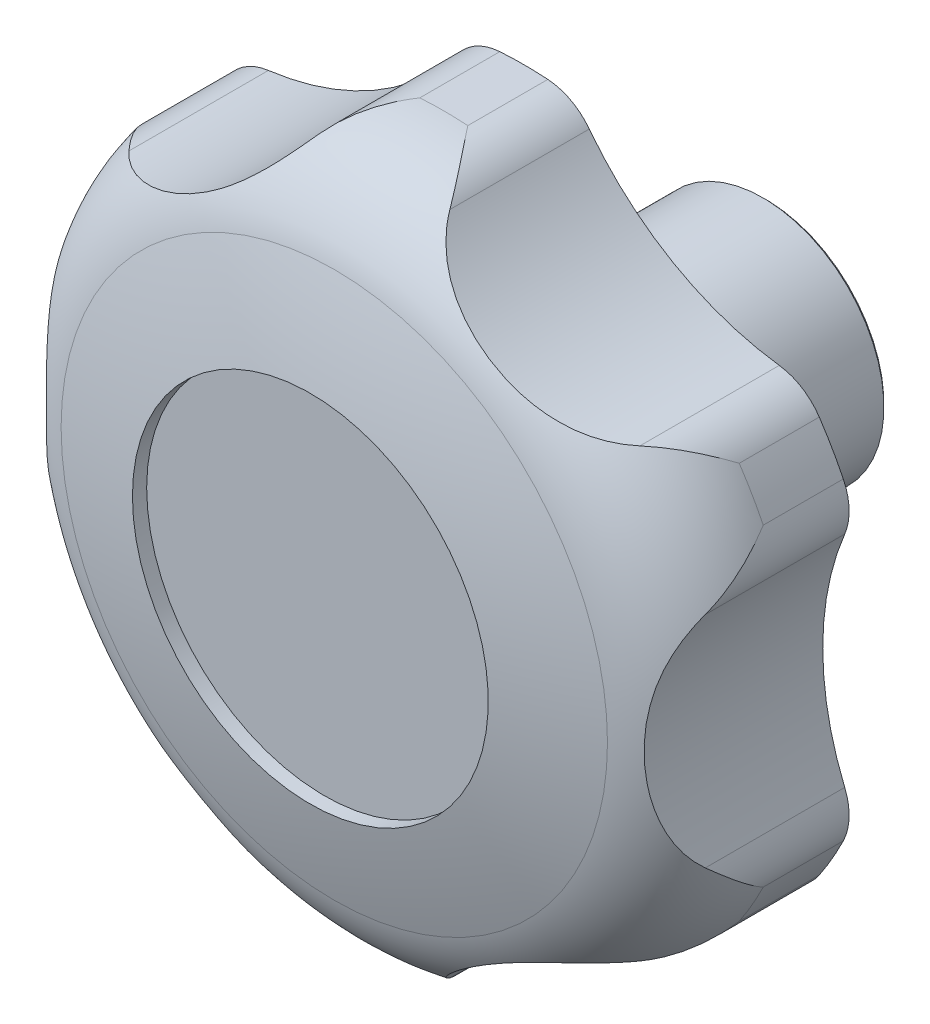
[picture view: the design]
ISO-10303-21;
HEADER;
FILE_DESCRIPTION(('STEP AP214'),'2;1');
FILE_NAME('part.step','',(''),(''),'','','');
FILE_SCHEMA(('AUTOMOTIVE_DESIGN { 1 0 10303 214 1 1 1 1 }'));
ENDSEC;
DATA;
#1=APPLICATION_CONTEXT('core data for automotive mechanical design processes');
#2=APPLICATION_PROTOCOL_DEFINITION('international standard','automotive_design',2000,#1);
#3=PRODUCT_CONTEXT('',#1,'mechanical');
#4=PRODUCT('Part','Part','',(#3));
#5=PRODUCT_RELATED_PRODUCT_CATEGORY('part','',(#4));
#6=PRODUCT_DEFINITION_FORMATION('','',#4);
#7=PRODUCT_DEFINITION_CONTEXT('part definition',#1,'design');
#8=PRODUCT_DEFINITION('design','',#6,#7);
#9=PRODUCT_DEFINITION_SHAPE('','',#8);
#10=(LENGTH_UNIT() NAMED_UNIT(*) SI_UNIT(.MILLI.,.METRE.));
#11=(NAMED_UNIT(*) PLANE_ANGLE_UNIT() SI_UNIT($,.RADIAN.));
#12=(NAMED_UNIT(*) SI_UNIT($,.STERADIAN.) SOLID_ANGLE_UNIT());
#13=UNCERTAINTY_MEASURE_WITH_UNIT(LENGTH_MEASURE(1.E-05),#10,'distance_accuracy_value','');
#14=(GEOMETRIC_REPRESENTATION_CONTEXT(3) GLOBAL_UNCERTAINTY_ASSIGNED_CONTEXT((#13)) GLOBAL_UNIT_ASSIGNED_CONTEXT((#10,
#11,#12)) REPRESENTATION_CONTEXT('',''));
#15=CARTESIAN_POINT('',(0.,0.,0.));
#16=DIRECTION('',(0.,0.,1.));
#17=DIRECTION('',(1.,0.,0.));
#18=AXIS2_PLACEMENT_3D('',#15,#16,#17);
#19=CARTESIAN_POINT('',(0.,0.,39.106347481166));
#20=DIRECTION('',(0.,0.,1.));
#21=DIRECTION('',(-1.,0.,0.));
#22=AXIS2_PLACEMENT_3D('',#19,#20,#21);
#23=CYLINDRICAL_SURFACE('',#22,25.);
#24=CARTESIAN_POINT('',(0.,0.,17.));
#25=DIRECTION('',(0.,0.,1.));
#26=DIRECTION('',(-1.,0.,0.));
#27=AXIS2_PLACEMENT_3D('',#24,#25,#26);
#28=CIRCLE('',#27,25.);
#29=CARTESIAN_POINT('',(1.68710504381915,24.9430085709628,17.));
#30=VERTEX_POINT('',#29);
#31=CARTESIAN_POINT('',(-1.68710504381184,24.9430085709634,17.));
#32=VERTEX_POINT('',#31);
#33=EDGE_CURVE('E418',#30,#32,#28,.T.);
#34=ORIENTED_EDGE('',*,*,#33,.T.);
#35=DIRECTION('',(0.,0.,1.));
#36=VECTOR('',#35,1.);
#37=CARTESIAN_POINT('',(-1.68710504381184,24.9430085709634,0.));
#38=LINE('',#37,#36);
#39=CARTESIAN_POINT('',(-1.68710504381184,24.9430085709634,22.6238207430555));
#40=VERTEX_POINT('',#39);
#41=EDGE_CURVE('E214',#32,#40,#38,.T.);
#42=ORIENTED_EDGE('',*,*,#41,.T.);
#43=CARTESIAN_POINT('',(0.,0.,22.6238207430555));
#44=DIRECTION('',(0.,0.,1.));
#45=DIRECTION('',(-1.,0.,0.));
#46=AXIS2_PLACEMENT_3D('',#43,#44,#45);
#47=CIRCLE('',#46,25.);
#48=CARTESIAN_POINT('',(1.68710504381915,24.9430085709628,22.6238207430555));
#49=VERTEX_POINT('',#48);
#50=EDGE_CURVE('E433',#49,#40,#47,.T.);
#51=ORIENTED_EDGE('',*,*,#50,.F.);
#52=DIRECTION('',(0.,0.,1.));
#53=VECTOR('',#52,1.);
#54=CARTESIAN_POINT('',(1.68710504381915,24.9430085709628,0.));
#55=LINE('',#54,#53);
#56=EDGE_CURVE('E465',#30,#49,#55,.T.);
#57=ORIENTED_EDGE('',*,*,#56,.F.);
#58=EDGE_LOOP('',(#34,#42,#51,#57));
#59=FACE_BOUND('',#58,.T.);
#60=ADVANCED_FACE('F14',(#59),#23,.T.);
#61=CARTESIAN_POINT('',(22.444831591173,11.0104284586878,17.));
#62=VERTEX_POINT('',#61);
#63=CARTESIAN_POINT('',(20.7577265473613,13.9325801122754,17.));
#64=VERTEX_POINT('',#63);
#65=EDGE_CURVE('E422',#62,#64,#28,.T.);
#66=ORIENTED_EDGE('',*,*,#65,.T.);
#67=DIRECTION('',(0.,0.,1.));
#68=VECTOR('',#67,1.);
#69=CARTESIAN_POINT('',(20.7577265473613,13.9325801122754,0.));
#70=LINE('',#69,#68);
#71=CARTESIAN_POINT('',(20.7577265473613,13.9325801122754,22.6238207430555));
#72=VERTEX_POINT('',#71);
#73=EDGE_CURVE('E450',#64,#72,#70,.T.);
#74=ORIENTED_EDGE('',*,*,#73,.T.);
#75=CARTESIAN_POINT('',(22.444831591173,11.0104284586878,22.6238207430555));
#76=VERTEX_POINT('',#75);
#77=EDGE_CURVE('E480',#76,#72,#47,.T.);
#78=ORIENTED_EDGE('',*,*,#77,.F.);
#79=DIRECTION('',(0.,0.,1.));
#80=VECTOR('',#79,1.);
#81=CARTESIAN_POINT('',(22.444831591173,11.0104284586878,0.));
#82=LINE('',#81,#80);
#83=EDGE_CURVE('E452',#62,#76,#82,.T.);
#84=ORIENTED_EDGE('',*,*,#83,.F.);
#85=EDGE_LOOP('',(#66,#74,#78,#84));
#86=FACE_BOUND('',#85,.T.);
#87=ADVANCED_FACE('F393',(#86),#23,.T.);
#88=CARTESIAN_POINT('',(20.7577265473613,-13.9325801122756,17.));
#89=VERTEX_POINT('',#88);
#90=CARTESIAN_POINT('',(22.444831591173,-11.0104284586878,17.));
#91=VERTEX_POINT('',#90);
#92=EDGE_CURVE('E436',#89,#91,#28,.T.);
#93=ORIENTED_EDGE('',*,*,#92,.T.);
#94=DIRECTION('',(0.,0.,1.));
#95=VECTOR('',#94,1.);
#96=CARTESIAN_POINT('',(22.444831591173,-11.0104284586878,0.));
#97=LINE('',#96,#95);
#98=CARTESIAN_POINT('',(22.444831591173,-11.0104284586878,22.6238207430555));
#99=VERTEX_POINT('',#98);
#100=EDGE_CURVE('E534',#91,#99,#97,.T.);
#101=ORIENTED_EDGE('',*,*,#100,.T.);
#102=CARTESIAN_POINT('',(20.7577265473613,-13.9325801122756,22.6238207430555));
#103=VERTEX_POINT('',#102);
#104=EDGE_CURVE('E481',#103,#99,#47,.T.);
#105=ORIENTED_EDGE('',*,*,#104,.F.);
#106=DIRECTION('',(0.,0.,1.));
#107=VECTOR('',#106,1.);
#108=CARTESIAN_POINT('',(20.7577265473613,-13.9325801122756,0.));
#109=LINE('',#108,#107);
#110=EDGE_CURVE('E532',#89,#103,#109,.T.);
#111=ORIENTED_EDGE('',*,*,#110,.F.);
#112=EDGE_LOOP('',(#93,#101,#105,#111));
#113=FACE_BOUND('',#112,.T.);
#114=ADVANCED_FACE('F401',(#113),#23,.T.);
#115=CARTESIAN_POINT('',(-1.68710504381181,-24.9430085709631,17.));
#116=VERTEX_POINT('',#115);
#117=CARTESIAN_POINT('',(1.68710504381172,-24.9430085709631,17.));
#118=VERTEX_POINT('',#117);
#119=EDGE_CURVE('E429',#116,#118,#28,.T.);
#120=ORIENTED_EDGE('',*,*,#119,.T.);
#121=DIRECTION('',(0.,0.,1.));
#122=VECTOR('',#121,1.);
#123=CARTESIAN_POINT('',(1.68710504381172,-24.9430085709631,0.));
#124=LINE('',#123,#122);
#125=CARTESIAN_POINT('',(1.68710504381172,-24.9430085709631,22.6238207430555));
#126=VERTEX_POINT('',#125);
#127=EDGE_CURVE('E524',#118,#126,#124,.T.);
#128=ORIENTED_EDGE('',*,*,#127,.T.);
#129=CARTESIAN_POINT('',(-1.68710504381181,-24.9430085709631,22.6238207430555));
#130=VERTEX_POINT('',#129);
#131=EDGE_CURVE('E485',#130,#126,#47,.T.);
#132=ORIENTED_EDGE('',*,*,#131,.F.);
#133=DIRECTION('',(0.,0.,1.));
#134=VECTOR('',#133,1.);
#135=CARTESIAN_POINT('',(-1.68710504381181,-24.9430085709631,0.));
#136=LINE('',#135,#134);
#137=EDGE_CURVE('E522',#116,#130,#136,.T.);
#138=ORIENTED_EDGE('',*,*,#137,.F.);
#139=EDGE_LOOP('',(#120,#128,#132,#138));
#140=FACE_BOUND('',#139,.T.);
#141=ADVANCED_FACE('F413',(#140),#23,.T.);
#142=CARTESIAN_POINT('',(-22.4448315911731,-11.0104284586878,17.));
#143=VERTEX_POINT('',#142);
#144=CARTESIAN_POINT('',(-20.7577265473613,-13.9325801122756,17.));
#145=VERTEX_POINT('',#144);
#146=EDGE_CURVE('E421',#143,#145,#28,.T.);
#147=ORIENTED_EDGE('',*,*,#146,.T.);
#148=DIRECTION('',(0.,0.,1.));
#149=VECTOR('',#148,1.);
#150=CARTESIAN_POINT('',(-20.7577265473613,-13.9325801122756,0.));
#151=LINE('',#150,#149);
#152=CARTESIAN_POINT('',(-20.7577265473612,-13.9325801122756,22.6238207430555));
#153=VERTEX_POINT('',#152);
#154=EDGE_CURVE('E514',#145,#153,#151,.T.);
#155=ORIENTED_EDGE('',*,*,#154,.T.);
#156=CARTESIAN_POINT('',(-22.4448315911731,-11.0104284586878,22.6238207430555));
#157=VERTEX_POINT('',#156);
#158=EDGE_CURVE('E434',#157,#153,#47,.T.);
#159=ORIENTED_EDGE('',*,*,#158,.F.);
#160=DIRECTION('',(0.,0.,1.));
#161=VECTOR('',#160,1.);
#162=CARTESIAN_POINT('',(-22.4448315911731,-11.0104284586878,0.));
#163=LINE('',#162,#161);
#164=EDGE_CURVE('E512',#143,#157,#163,.T.);
#165=ORIENTED_EDGE('',*,*,#164,.F.);
#166=EDGE_LOOP('',(#147,#155,#159,#165));
#167=FACE_BOUND('',#166,.T.);
#168=ADVANCED_FACE('F405',(#167),#23,.T.);
#169=CARTESIAN_POINT('',(-20.7577265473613,13.9325801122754,17.));
#170=VERTEX_POINT('',#169);
#171=CARTESIAN_POINT('',(-22.4448315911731,11.0104284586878,17.));
#172=VERTEX_POINT('',#171);
#173=EDGE_CURVE('E210',#170,#172,#28,.T.);
#174=ORIENTED_EDGE('',*,*,#173,.T.);
#175=DIRECTION('',(0.,0.,1.));
#176=VECTOR('',#175,1.);
#177=CARTESIAN_POINT('',(-22.4448315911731,11.0104284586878,0.));
#178=LINE('',#177,#176);
#179=CARTESIAN_POINT('',(-22.4448315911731,11.0104284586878,22.6238207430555));
#180=VERTEX_POINT('',#179);
#181=EDGE_CURVE('E416',#172,#180,#178,.T.);
#182=ORIENTED_EDGE('',*,*,#181,.T.);
#183=CARTESIAN_POINT('',(-20.7577265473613,13.9325801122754,22.6238207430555));
#184=VERTEX_POINT('',#183);
#185=EDGE_CURVE('E428',#184,#180,#47,.T.);
#186=ORIENTED_EDGE('',*,*,#185,.F.);
#187=DIRECTION('',(0.,0.,1.));
#188=VECTOR('',#187,1.);
#189=CARTESIAN_POINT('',(-20.7577265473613,13.9325801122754,0.));
#190=LINE('',#189,#188);
#191=EDGE_CURVE('E203',#170,#184,#190,.T.);
#192=ORIENTED_EDGE('',*,*,#191,.F.);
#193=EDGE_LOOP('',(#174,#182,#186,#192));
#194=FACE_BOUND('',#193,.T.);
#195=ADVANCED_FACE('F395',(#194),#23,.T.);
#196=CARTESIAN_POINT('',(0.,11.,17.));
#197=DIRECTION('',(0.,0.,1.));
#198=DIRECTION('',(-1.,0.,0.));
#199=AXIS2_PLACEMENT_3D('',#196,#197,#198);
#200=PLANE('',#199);
#201=ORIENTED_EDGE('',*,*,#33,.F.);
#202=CARTESIAN_POINT('',(1.41716823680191,20.9521271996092,17.));
#203=DIRECTION('',(0.,0.,1.));
#204=DIRECTION('',(-1.,0.,0.));
#205=AXIS2_PLACEMENT_3D('',#202,#203,#204);
#206=CIRCLE('',#205,4.);
#207=CARTESIAN_POINT('',(4.59764019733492,23.377946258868,17.));
#208=VERTEX_POINT('',#207);
#209=EDGE_CURVE('E379',#30,#208,#206,.F.);
#210=ORIENTED_EDGE('',*,*,#209,.T.);
#211=CARTESIAN_POINT('',(20.5,35.507041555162,17.));
#212=DIRECTION('',(0.,0.,1.));
#213=DIRECTION('',(-1.,0.,0.));
#214=AXIS2_PLACEMENT_3D('',#211,#212,#213);
#215=CIRCLE('',#214,20.);
#216=CARTESIAN_POINT('',(17.9470752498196,15.6706463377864,17.));
#217=VERTEX_POINT('',#216);
#218=EDGE_CURVE('E457',#217,#208,#215,.F.);
#219=ORIENTED_EDGE('',*,*,#218,.F.);
#220=CARTESIAN_POINT('',(17.4364902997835,11.7033672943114,17.));
#221=DIRECTION('',(0.,0.,1.));
#222=DIRECTION('',(-1.,0.,0.));
#223=AXIS2_PLACEMENT_3D('',#220,#221,#222);
#224=CIRCLE('',#223,4.);
#225=EDGE_CURVE('E370',#217,#64,#224,.F.);
#226=ORIENTED_EDGE('',*,*,#225,.T.);
#227=ORIENTED_EDGE('',*,*,#65,.F.);
#228=CARTESIAN_POINT('',(18.8536585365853,9.24875990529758,17.));
#229=DIRECTION('',(0.,0.,1.));
#230=DIRECTION('',(-1.,0.,0.));
#231=AXIS2_PLACEMENT_3D('',#228,#229,#230);
#232=CIRCLE('',#231,4.);
#233=CARTESIAN_POINT('',(22.5447154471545,7.70729992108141,17.));
#234=VERTEX_POINT('',#233);
#235=EDGE_CURVE('E352',#62,#234,#232,.F.);
#236=ORIENTED_EDGE('',*,*,#235,.T.);
#237=CARTESIAN_POINT('',(41.,0.,17.));
#238=DIRECTION('',(0.,0.,1.));
#239=DIRECTION('',(-1.,0.,0.));
#240=AXIS2_PLACEMENT_3D('',#237,#238,#239);
#241=CIRCLE('',#240,20.);
#242=CARTESIAN_POINT('',(22.5447154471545,-7.70729992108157,17.));
#243=VERTEX_POINT('',#242);
#244=EDGE_CURVE('E564',#243,#234,#241,.F.);
#245=ORIENTED_EDGE('',*,*,#244,.F.);
#246=CARTESIAN_POINT('',(18.8536585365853,-9.2487599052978,17.));
#247=DIRECTION('',(0.,0.,1.));
#248=DIRECTION('',(-1.,0.,0.));
#249=AXIS2_PLACEMENT_3D('',#246,#247,#248);
#250=CIRCLE('',#249,4.);
#251=EDGE_CURVE('E343',#243,#91,#250,.F.);
#252=ORIENTED_EDGE('',*,*,#251,.T.);
#253=ORIENTED_EDGE('',*,*,#92,.F.);
#254=CARTESIAN_POINT('',(17.4364902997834,-11.7033672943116,17.));
#255=DIRECTION('',(0.,0.,1.));
#256=DIRECTION('',(-1.,0.,0.));
#257=AXIS2_PLACEMENT_3D('',#254,#255,#256);
#258=CIRCLE('',#257,4.);
#259=CARTESIAN_POINT('',(17.9470752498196,-15.6706463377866,17.));
#260=VERTEX_POINT('',#259);
#261=EDGE_CURVE('E320',#89,#260,#258,.F.);
#262=ORIENTED_EDGE('',*,*,#261,.T.);
#263=CARTESIAN_POINT('',(20.5,-35.5070415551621,17.));
#264=DIRECTION('',(0.,0.,1.));
#265=DIRECTION('',(-1.,0.,0.));
#266=AXIS2_PLACEMENT_3D('',#263,#264,#265);
#267=CIRCLE('',#266,20.);
#268=CARTESIAN_POINT('',(4.59764019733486,-23.3779462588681,17.));
#269=VERTEX_POINT('',#268);
#270=EDGE_CURVE('E563',#269,#260,#267,.F.);
#271=ORIENTED_EDGE('',*,*,#270,.F.);
#272=CARTESIAN_POINT('',(1.41716823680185,-20.9521271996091,17.));
#273=DIRECTION('',(0.,0.,1.));
#274=DIRECTION('',(-1.,0.,0.));
#275=AXIS2_PLACEMENT_3D('',#272,#273,#274);
#276=CIRCLE('',#275,4.);
#277=EDGE_CURVE('E310',#269,#118,#276,.F.);
#278=ORIENTED_EDGE('',*,*,#277,.T.);
#279=ORIENTED_EDGE('',*,*,#119,.F.);
#280=CARTESIAN_POINT('',(-1.41716823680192,-20.9521271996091,17.));
#281=DIRECTION('',(0.,0.,1.));
#282=DIRECTION('',(-1.,0.,0.));
#283=AXIS2_PLACEMENT_3D('',#280,#281,#282);
#284=CIRCLE('',#283,4.);
#285=CARTESIAN_POINT('',(-4.59764019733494,-23.3779462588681,17.));
#286=VERTEX_POINT('',#285);
#287=EDGE_CURVE('E299',#116,#286,#284,.F.);
#288=ORIENTED_EDGE('',*,*,#287,.T.);
#289=CARTESIAN_POINT('',(-20.5,-35.5070415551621,17.));
#290=DIRECTION('',(0.,0.,1.));
#291=DIRECTION('',(-1.,0.,0.));
#292=AXIS2_PLACEMENT_3D('',#289,#290,#291);
#293=CIRCLE('',#292,20.);
#294=CARTESIAN_POINT('',(-17.9470752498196,-15.6706463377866,17.));
#295=VERTEX_POINT('',#294);
#296=EDGE_CURVE('E565',#295,#286,#293,.F.);
#297=ORIENTED_EDGE('',*,*,#296,.F.);
#298=CARTESIAN_POINT('',(-17.4364902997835,-11.7033672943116,17.));
#299=DIRECTION('',(0.,0.,1.));
#300=DIRECTION('',(-1.,0.,0.));
#301=AXIS2_PLACEMENT_3D('',#298,#299,#300);
#302=CIRCLE('',#301,4.);
#303=EDGE_CURVE('E300',#295,#145,#302,.F.);
#304=ORIENTED_EDGE('',*,*,#303,.T.);
#305=ORIENTED_EDGE('',*,*,#146,.F.);
#306=CARTESIAN_POINT('',(-18.8536585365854,-9.2487599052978,17.));
#307=DIRECTION('',(0.,0.,1.));
#308=DIRECTION('',(-1.,0.,0.));
#309=AXIS2_PLACEMENT_3D('',#306,#307,#308);
#310=CIRCLE('',#309,4.);
#311=CARTESIAN_POINT('',(-22.5447154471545,-7.70729992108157,17.));
#312=VERTEX_POINT('',#311);
#313=EDGE_CURVE('E794',#143,#312,#310,.F.);
#314=ORIENTED_EDGE('',*,*,#313,.T.);
#315=CARTESIAN_POINT('',(-41.,0.,17.));
#316=DIRECTION('',(0.,0.,1.));
#317=DIRECTION('',(-1.,0.,0.));
#318=AXIS2_PLACEMENT_3D('',#315,#316,#317);
#319=CIRCLE('',#318,20.);
#320=CARTESIAN_POINT('',(-22.5447154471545,7.70729992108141,17.));
#321=VERTEX_POINT('',#320);
#322=EDGE_CURVE('E194',#321,#312,#319,.F.);
#323=ORIENTED_EDGE('',*,*,#322,.F.);
#324=CARTESIAN_POINT('',(-18.8536585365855,9.2487599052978,17.));
#325=DIRECTION('',(0.,0.,1.));
#326=DIRECTION('',(-1.,0.,0.));
#327=AXIS2_PLACEMENT_3D('',#324,#325,#326);
#328=CIRCLE('',#327,4.);
#329=EDGE_CURVE('E212',#321,#172,#328,.F.);
#330=ORIENTED_EDGE('',*,*,#329,.T.);
#331=ORIENTED_EDGE('',*,*,#173,.F.);
#332=CARTESIAN_POINT('',(-17.4364902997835,11.7033672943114,17.));
#333=DIRECTION('',(0.,0.,1.));
#334=DIRECTION('',(-1.,0.,0.));
#335=AXIS2_PLACEMENT_3D('',#332,#333,#334);
#336=CIRCLE('',#335,4.);
#337=CARTESIAN_POINT('',(-17.9470752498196,15.6706463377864,17.));
#338=VERTEX_POINT('',#337);
#339=EDGE_CURVE('E199',#170,#338,#336,.F.);
#340=ORIENTED_EDGE('',*,*,#339,.T.);
#341=CARTESIAN_POINT('',(-20.5,35.507041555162,17.));
#342=DIRECTION('',(0.,0.,1.));
#343=DIRECTION('',(-1.,0.,0.));
#344=AXIS2_PLACEMENT_3D('',#341,#342,#343);
#345=CIRCLE('',#344,20.);
#346=CARTESIAN_POINT('',(-4.59764019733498,23.377946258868,17.));
#347=VERTEX_POINT('',#346);
#348=EDGE_CURVE('E184',#347,#338,#345,.F.);
#349=ORIENTED_EDGE('',*,*,#348,.F.);
#350=CARTESIAN_POINT('',(-1.41716823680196,20.9521271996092,17.));
#351=DIRECTION('',(0.,0.,1.));
#352=DIRECTION('',(-1.,0.,0.));
#353=AXIS2_PLACEMENT_3D('',#350,#351,#352);
#354=CIRCLE('',#353,4.);
#355=EDGE_CURVE('E195',#347,#32,#354,.F.);
#356=ORIENTED_EDGE('',*,*,#355,.T.);
#357=EDGE_LOOP('',(#201,#210,#219,#226,#227,#236,#245,#252,#253,#262,#271,#278,#279,#288,#297,
#304,#305,#314,#323,#330,#331,#340,#349,#356));
#358=FACE_BOUND('',#357,.T.);
#359=CARTESIAN_POINT('',(0.,0.,17.));
#360=DIRECTION('',(0.,0.,1.));
#361=DIRECTION('',(-1.,0.,0.));
#362=AXIS2_PLACEMENT_3D('',#359,#360,#361);
#363=CIRCLE('',#362,11.);
#364=CARTESIAN_POINT('',(-11.,0.,17.));
#365=VERTEX_POINT('',#364);
#366=EDGE_CURVE('E499',#365,#365,#363,.T.);
#367=ORIENTED_EDGE('',*,*,#366,.T.);
#368=EDGE_LOOP('',(#367));
#369=FACE_BOUND('',#368,.T.);
#370=ADVANCED_FACE('F16',(#358,#369),#200,.F.);
#371=CARTESIAN_POINT('',(0.,0.,39.106347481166));
#372=DIRECTION('',(0.,0.,1.));
#373=DIRECTION('',(-1.,0.,0.));
#374=AXIS2_PLACEMENT_3D('',#371,#372,#373);
#375=CYLINDRICAL_SURFACE('',#374,11.);
#376=CARTESIAN_POINT('',(0.,0.,15.));
#377=DIRECTION('',(0.,0.,1.));
#378=DIRECTION('',(-1.,0.,0.));
#379=AXIS2_PLACEMENT_3D('',#376,#377,#378);
#380=CIRCLE('',#379,11.);
#381=CARTESIAN_POINT('',(-11.,0.,15.));
#382=VERTEX_POINT('',#381);
#383=EDGE_CURVE('E497',#382,#382,#380,.T.);
#384=ORIENTED_EDGE('',*,*,#383,.T.);
#385=EDGE_LOOP('',(#384));
#386=FACE_BOUND('',#385,.T.);
#387=ORIENTED_EDGE('',*,*,#366,.F.);
#388=EDGE_LOOP('',(#387));
#389=FACE_BOUND('',#388,.T.);
#390=ADVANCED_FACE('F412',(#386,#389),#375,.T.);
#391=CARTESIAN_POINT('',(0.,8.5,15.));
#392=DIRECTION('',(0.,0.,1.));
#393=DIRECTION('',(-1.,0.,0.));
#394=AXIS2_PLACEMENT_3D('',#391,#392,#393);
#395=PLANE('',#394);
#396=ORIENTED_EDGE('',*,*,#383,.F.);
#397=EDGE_LOOP('',(#396));
#398=FACE_BOUND('',#397,.T.);
#399=CARTESIAN_POINT('',(0.,0.,15.));
#400=DIRECTION('',(0.,0.,1.));
#401=DIRECTION('',(-1.,0.,0.));
#402=AXIS2_PLACEMENT_3D('',#399,#400,#401);
#403=CIRCLE('',#402,8.5);
#404=CARTESIAN_POINT('',(-8.5,0.,15.));
#405=VERTEX_POINT('',#404);
#406=EDGE_CURVE('E494',#405,#405,#403,.T.);
#407=ORIENTED_EDGE('',*,*,#406,.T.);
#408=EDGE_LOOP('',(#407));
#409=FACE_BOUND('',#408,.T.);
#410=ADVANCED_FACE('F595',(#398,#409),#395,.F.);
#411=CARTESIAN_POINT('',(0.,0.,39.106347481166));
#412=DIRECTION('',(0.,0.,1.));
#413=DIRECTION('',(-1.,0.,0.));
#414=AXIS2_PLACEMENT_3D('',#411,#412,#413);
#415=CYLINDRICAL_SURFACE('',#414,8.5);
#416=CARTESIAN_POINT('',(0.,0.,0.200000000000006));
#417=DIRECTION('',(0.,0.,1.));
#418=DIRECTION('',(-1.,0.,0.));
#419=AXIS2_PLACEMENT_3D('',#416,#417,#418);
#420=CIRCLE('',#419,8.5);
#421=CARTESIAN_POINT('',(-8.5,0.,0.200000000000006));
#422=VERTEX_POINT('',#421);
#423=EDGE_CURVE('E491',#422,#422,#420,.T.);
#424=ORIENTED_EDGE('',*,*,#423,.T.);
#425=EDGE_LOOP('',(#424));
#426=FACE_BOUND('',#425,.T.);
#427=ORIENTED_EDGE('',*,*,#406,.F.);
#428=EDGE_LOOP('',(#427));
#429=FACE_BOUND('',#428,.T.);
#430=ADVANCED_FACE('F591',(#426,#429),#415,.T.);
#431=CARTESIAN_POINT('',(0.,0.,0.));
#432=DIRECTION('',(0.,0.,1.));
#433=DIRECTION('',(-1.,0.,0.));
#434=AXIS2_PLACEMENT_3D('',#431,#432,#433);
#435=CONICAL_SURFACE('',#434,8.3,0.785398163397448);
#436=ORIENTED_EDGE('',*,*,#423,.F.);
#437=EDGE_LOOP('',(#436));
#438=FACE_BOUND('',#437,.T.);
#439=CARTESIAN_POINT('',(0.,0.,0.));
#440=DIRECTION('',(0.,0.,1.));
#441=DIRECTION('',(-1.,0.,0.));
#442=AXIS2_PLACEMENT_3D('',#439,#440,#441);
#443=CIRCLE('',#442,8.3);
#444=CARTESIAN_POINT('',(-8.3,0.,0.));
#445=VERTEX_POINT('',#444);
#446=EDGE_CURVE('E488',#445,#445,#443,.T.);
#447=ORIENTED_EDGE('',*,*,#446,.T.);
#448=EDGE_LOOP('',(#447));
#449=FACE_BOUND('',#448,.T.);
#450=ADVANCED_FACE('F585',(#438,#449),#435,.T.);
#451=CARTESIAN_POINT('',(0.,0.,0.));
#452=DIRECTION('',(0.,0.,1.));
#453=DIRECTION('',(-1.,0.,0.));
#454=AXIS2_PLACEMENT_3D('',#451,#452,#453);
#455=PLANE('',#454);
#456=ORIENTED_EDGE('',*,*,#446,.F.);
#457=EDGE_LOOP('',(#456));
#458=FACE_BOUND('',#457,.T.);
#459=ADVANCED_FACE('F578',(#458),#455,.F.);
#460=CARTESIAN_POINT('',(0.,0.,-36.6463385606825));
#461=DIRECTION('',(0.,0.,1.));
#462=DIRECTION('',(-1.,0.,0.));
#463=AXIS2_PLACEMENT_3D('',#460,#461,#462);
#464=DEGENERATE_TOROIDAL_SURFACE('',#463,1.19964241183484,70.,.F.);
#465=CARTESIAN_POINT('',(0.,0.,30.317216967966));
#466=DIRECTION('',(0.,0.,1.));
#467=DIRECTION('',(-1.,0.,0.));
#468=AXIS2_PLACEMENT_3D('',#465,#466,#467);
#469=CIRCLE('',#468,19.1935483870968);
#470=CARTESIAN_POINT('',(-19.1935483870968,0.,30.317216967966));
#471=VERTEX_POINT('',#470);
#472=EDGE_CURVE('E484',#471,#471,#469,.T.);
#473=ORIENTED_EDGE('',*,*,#472,.T.);
#474=EDGE_LOOP('',(#473));
#475=FACE_BOUND('',#474,.T.);
#476=CARTESIAN_POINT('',(0.,0.,32.));
#477=DIRECTION('',(0.,0.,1.));
#478=DIRECTION('',(-1.,0.,0.));
#479=AXIS2_PLACEMENT_3D('',#476,#477,#478);
#480=CIRCLE('',#479,12.5);
#481=CARTESIAN_POINT('',(-12.5,0.,32.));
#482=VERTEX_POINT('',#481);
#483=EDGE_CURVE('E424',#482,#482,#480,.T.);
#484=ORIENTED_EDGE('',*,*,#483,.F.);
#485=EDGE_LOOP('',(#484));
#486=FACE_BOUND('',#485,.T.);
#487=ADVANCED_FACE('F576',(#475,#486),#464,.F.);
#488=CARTESIAN_POINT('',(0.,0.,22.6238207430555));
#489=DIRECTION('',(0.,0.,1.));
#490=DIRECTION('',(-1.,0.,0.));
#491=AXIS2_PLACEMENT_3D('',#488,#489,#490);
#492=TOROIDAL_SURFACE('',#491,17.,8.);
#493=CARTESIAN_POINT('',(1.6871050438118,24.9430085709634,22.6238207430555));
#494=CARTESIAN_POINT('',(1.69073909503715,24.942762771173,22.6285417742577));
#495=CARTESIAN_POINT('',(1.69437284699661,24.9425120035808,22.6332628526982));
#496=CARTESIAN_POINT('',(1.87946401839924,24.9294846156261,22.8737614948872));
#497=CARTESIAN_POINT('',(2.06014899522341,24.9043241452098,23.1096462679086));
#498=CARTESIAN_POINT('',(2.41740743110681,24.829350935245,23.5806622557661));
#499=CARTESIAN_POINT('',(2.59397934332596,24.7795290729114,23.8157931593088));
#500=CARTESIAN_POINT('',(2.94077285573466,24.6551804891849,24.2848490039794));
#501=CARTESIAN_POINT('',(3.11098412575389,24.5806153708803,24.5187714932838));
#502=CARTESIAN_POINT('',(3.44192774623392,24.4068725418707,24.9839347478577));
#503=CARTESIAN_POINT('',(3.60266612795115,24.3077107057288,25.2151771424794));
#504=CARTESIAN_POINT('',(3.91224597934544,24.0843947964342,25.6747372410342));
#505=CARTESIAN_POINT('',(4.0610536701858,23.9601730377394,25.9030452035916));
#506=CARTESIAN_POINT('',(4.27214053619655,23.7554678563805,26.2414437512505));
#507=CARTESIAN_POINT('',(4.34042478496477,23.6842446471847,26.3534648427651));
#508=CARTESIAN_POINT('',(4.47256192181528,23.5356227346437,26.5760997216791));
#509=CARTESIAN_POINT('',(4.53641283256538,23.4582213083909,26.6867128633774));
#510=CARTESIAN_POINT('',(4.59779273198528,23.377746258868,26.796508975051));
#511=B_SPLINE_CURVE_WITH_KNOTS('',3,(#493,#494,#495,#496,#497,#498,#499,#500,#501,#502,#503,
#504,#505,#506,#507,#508,#509,#510),.UNSPECIFIED.,.F.,.F.,(4,2,2,2,2,2,2,2,4),(0.,
0.0178885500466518,0.911260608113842,1.80496339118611,2.70005957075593,3.5945795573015,
4.49154874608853,4.93921044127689,5.38707053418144),.UNSPECIFIED.);
#512=CARTESIAN_POINT('',(4.59764019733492,23.377946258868,26.796236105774));
#513=VERTEX_POINT('',#512);
#514=EDGE_CURVE('E373',#49,#513,#511,.T.);
#515=ORIENTED_EDGE('',*,*,#514,.F.);
#516=ORIENTED_EDGE('',*,*,#50,.T.);
#517=CARTESIAN_POINT('',(-4.59779273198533,23.377746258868,26.796508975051));
#518=CARTESIAN_POINT('',(-4.49325605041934,23.5147571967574,26.6095689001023));
#519=CARTESIAN_POINT('',(-4.38160827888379,23.6428640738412,26.4202643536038));
#520=CARTESIAN_POINT('',(-4.14644934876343,23.8811358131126,26.0379860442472));
#521=CARTESIAN_POINT('',(-4.02294674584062,23.9913134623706,25.8450150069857));
#522=CARTESIAN_POINT('',(-3.76657567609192,24.1935565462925,25.4566398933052));
#523=CARTESIAN_POINT('',(-3.63372939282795,24.2856630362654,25.2612424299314));
#524=CARTESIAN_POINT('',(-3.36033897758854,24.4520846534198,24.8682984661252));
#525=CARTESIAN_POINT('',(-3.21979446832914,24.5263989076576,24.670751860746));
#526=CARTESIAN_POINT('',(-2.85660155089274,24.6919550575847,24.1688876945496));
#527=CARTESIAN_POINT('',(-2.62993299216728,24.7712789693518,23.8634968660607));
#528=CARTESIAN_POINT('',(-2.16859445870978,24.8880997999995,23.2513212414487));
#529=CARTESIAN_POINT('',(-1.93393522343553,24.9256507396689,22.9445387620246));
#530=CARTESIAN_POINT('',(-1.69437283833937,24.9425120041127,22.6332628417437));
#531=CARTESIAN_POINT('',(-1.6907390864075,24.9427627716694,22.6285417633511));
#532=CARTESIAN_POINT('',(-1.68710504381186,24.9430085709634,22.6238207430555));
#533=B_SPLINE_CURVE_WITH_KNOTS('',3,(#517,#518,#519,#520,#521,#522,#523,#524,#525,#526,#527,
#528,#529,#530,#531,#532),.UNSPECIFIED.,.F.,.F.,(4,2,2,2,2,2,2,4),(0.,0.762307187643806,
1.52406829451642,2.28407821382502,3.04412541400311,4.20717896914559,5.36872670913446,
5.38661525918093),.UNSPECIFIED.);
#534=CARTESIAN_POINT('',(-4.59764019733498,23.377946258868,26.7962361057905));
#535=VERTEX_POINT('',#534);
#536=EDGE_CURVE('E479',#535,#40,#533,.T.);
#537=ORIENTED_EDGE('',*,*,#536,.F.);
#538=CARTESIAN_POINT('',(-4.59748765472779,23.378146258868,26.79596321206));
#539=CARTESIAN_POINT('',(-4.68745740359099,23.260145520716,26.95706763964));
#540=CARTESIAN_POINT('',(-4.78366062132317,23.1367694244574,27.1105993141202));
#541=CARTESIAN_POINT('',(-4.98770324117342,22.8818683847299,27.4019414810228));
#542=CARTESIAN_POINT('',(-5.09552590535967,22.7503552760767,27.5397740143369));
#543=CARTESIAN_POINT('',(-5.32096382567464,22.4829423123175,27.7981438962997));
#544=CARTESIAN_POINT('',(-5.43845555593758,22.3471082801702,27.9188580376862));
#545=CARTESIAN_POINT('',(-5.68349322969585,22.0718238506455,28.1450671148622));
#546=CARTESIAN_POINT('',(-5.81104234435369,21.9323723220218,28.2505572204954));
#547=CARTESIAN_POINT('',(-6.07461744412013,21.6526168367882,28.4463134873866));
#548=CARTESIAN_POINT('',(-6.21059510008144,21.51232127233,28.5366571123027));
#549=CARTESIAN_POINT('',(-6.49077939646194,21.2318521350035,28.7036121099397));
#550=CARTESIAN_POINT('',(-6.6349853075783,21.0916785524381,28.7802246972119));
#551=CARTESIAN_POINT('',(-6.93128941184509,20.8124283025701,28.9209213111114));
#552=CARTESIAN_POINT('',(-7.08341006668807,20.6733562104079,28.9849669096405));
#553=CARTESIAN_POINT('',(-7.3944254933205,20.3978680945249,29.1012975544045));
#554=CARTESIAN_POINT('',(-7.5533218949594,20.2614527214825,29.1535797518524));
#555=CARTESIAN_POINT('',(-7.97410593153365,19.9116865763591,29.2754730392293));
#556=CARTESIAN_POINT('',(-8.24075460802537,19.7011167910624,29.3367475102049));
#557=CARTESIAN_POINT('',(-8.78734257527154,19.2919126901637,29.4355231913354));
#558=CARTESIAN_POINT('',(-9.06728849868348,19.0932844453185,29.4730124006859));
#559=CARTESIAN_POINT('',(-9.63920400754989,18.7093620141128,29.5268070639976));
#560=CARTESIAN_POINT('',(-9.93120356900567,18.5241046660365,29.5430559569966));
#561=CARTESIAN_POINT('',(-10.5246796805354,18.1688586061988,29.5553746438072));
#562=CARTESIAN_POINT('',(-10.8261546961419,17.9988674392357,29.551447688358));
#563=CARTESIAN_POINT('',(-11.4430750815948,17.6717820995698,29.522841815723));
#564=CARTESIAN_POINT('',(-11.7586802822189,17.5150254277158,29.497737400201));
#565=CARTESIAN_POINT('',(-12.3956325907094,17.2192723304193,29.4243261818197));
#566=CARTESIAN_POINT('',(-12.7169811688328,17.0802805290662,29.3760133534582));
#567=CARTESIAN_POINT('',(-13.3610540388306,16.8213387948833,29.2531219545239));
#568=CARTESIAN_POINT('',(-13.6837695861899,16.7013239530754,29.1786358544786));
#569=CARTESIAN_POINT('',(-14.3271826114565,16.4804364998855,28.9991434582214));
#570=CARTESIAN_POINT('',(-14.6478815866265,16.3795475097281,28.8941634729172));
#571=CARTESIAN_POINT('',(-15.1555460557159,16.2333162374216,28.697841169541));
#572=CARTESIAN_POINT('',(-15.3450819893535,16.1818181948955,28.6176170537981));
#573=CARTESIAN_POINT('',(-15.7195868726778,16.0857915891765,28.4435536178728));
#574=CARTESIAN_POINT('',(-15.9045573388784,16.0412606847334,28.3497188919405));
#575=CARTESIAN_POINT('',(-16.267646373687,15.9591067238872,28.1479603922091));
#576=CARTESIAN_POINT('',(-16.4457808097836,15.9214667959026,28.0400721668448));
#577=CARTESIAN_POINT('',(-16.7935555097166,15.8526864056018,27.8096475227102));
#578=CARTESIAN_POINT('',(-16.9631997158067,15.8215429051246,27.6871179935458));
#579=CARTESIAN_POINT('',(-17.2734523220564,15.768467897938,27.4418783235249));
#580=CARTESIAN_POINT('',(-17.4151836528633,15.7458950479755,27.3207286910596));
#581=CARTESIAN_POINT('',(-17.6889479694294,15.7050898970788,27.0669174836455));
#582=CARTESIAN_POINT('',(-17.820967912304,15.6868633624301,26.9342409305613));
#583=CARTESIAN_POINT('',(-17.9472752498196,15.6706205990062,26.796017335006));
#584=B_SPLINE_CURVE_WITH_KNOTS('',3,(#538,#539,#540,#541,#542,#543,#544,#545,#546,#547,#548,
#549,#550,#551,#552,#553,#554,#555,#556,#557,#558,#559,#560,#561,#562,#563,#564,#565,#566,#567,
#568,#569,#570,#571,#572,#573,#574,#575,#576,#577,#578,#579,#580,#581,#582,#583),.UNSPECIFIED.,
.F.,.F.,(4,2,2,2,2,2,2,2,2,2,2,2,2,2,2,2,2,2,2,2,2,2,4),(0.,0.656640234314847,1.31234690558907,
1.96069228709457,2.60924292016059,3.25436818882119,3.89943636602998,4.54644734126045,
5.19361483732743,6.22783106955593,7.26256869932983,8.3000561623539,9.33737647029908,
10.3960491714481,11.4549968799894,12.510240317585,13.5645759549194,14.2005435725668,
14.8362970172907,15.4704724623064,16.1043506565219,16.6671595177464,17.2307109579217),.UNSPECIFIED.);
#585=CARTESIAN_POINT('',(-17.9470752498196,15.6706463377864,26.796236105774));
#586=VERTEX_POINT('',#585);
#587=EDGE_CURVE('E258',#535,#586,#584,.T.);
#588=ORIENTED_EDGE('',*,*,#587,.T.);
#589=CARTESIAN_POINT('',(-20.7577265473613,13.9325801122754,22.6238207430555));
#590=CARTESIAN_POINT('',(-20.7556966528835,13.9356043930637,22.6285417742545));
#591=CARTESIAN_POINT('',(-20.7536626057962,13.938625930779,22.6332628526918));
#592=CARTESIAN_POINT('',(-20.6498349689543,14.0924058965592,22.8737614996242));
#593=CARTESIAN_POINT('',(-20.5377028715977,14.2363034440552,23.1096462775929));
#594=CARTESIAN_POINT('',(-20.2941449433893,14.5082117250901,23.5806622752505));
#595=CARTESIAN_POINT('',(-20.162711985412,14.636216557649,23.8157931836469));
#596=CARTESIAN_POINT('',(-19.8816261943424,14.8743742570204,24.2848490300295));
#597=CARTESIAN_POINT('',(-19.7319452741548,14.9844989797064,24.5187715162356));
#598=CARTESIAN_POINT('',(-19.4160077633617,15.1842331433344,24.9839347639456));
#599=CARTESIAN_POINT('',(-19.249761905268,15.2738557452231,25.2151771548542));
#600=CARTESIAN_POINT('',(-18.9015818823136,15.4302985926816,25.6747278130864));
#601=CARTESIAN_POINT('',(-18.7196066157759,15.4970566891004,25.9030264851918));
#602=CARTESIAN_POINT('',(-18.4367957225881,15.577508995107,26.2414114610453));
#603=CARTESIAN_POINT('',(-18.3409767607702,15.6010330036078,26.3534280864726));
#604=CARTESIAN_POINT('',(-18.1462066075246,15.6411562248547,26.576054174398));
#605=CARTESIAN_POINT('',(-18.0472540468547,15.657752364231,26.686662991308));
#606=CARTESIAN_POINT('',(-17.9468752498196,15.6706720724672,26.7964548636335));
#607=B_SPLINE_CURVE_WITH_KNOTS('',3,(#589,#590,#591,#592,#593,#594,#595,#596,#597,#598,#599,
#600,#601,#602,#603,#604,#605,#606),.UNSPECIFIED.,.F.,.F.,(4,2,2,2,2,2,2,2,4),(0.,
0.0178885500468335,0.911260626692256,1.80496342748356,2.70005959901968,3.59457955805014,
4.49151201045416,4.93915531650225,5.38699699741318),.UNSPECIFIED.);
#608=EDGE_CURVE('E202',#184,#586,#607,.T.);
#609=ORIENTED_EDGE('',*,*,#608,.F.);
#610=ORIENTED_EDGE('',*,*,#185,.T.);
#611=CARTESIAN_POINT('',(-22.5446319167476,7.7070999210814,26.7964712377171));
#612=CARTESIAN_POINT('',(-22.6110172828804,7.86613771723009,26.6095300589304));
#613=CARTESIAN_POINT('',(-22.6661359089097,8.0268818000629,26.4202244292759));
#614=CARTESIAN_POINT('',(-22.754903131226,8.34967281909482,26.037943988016));
#615=CARTESIAN_POINT('',(-22.7885670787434,8.5117187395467,25.8449719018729));
#616=CARTESIAN_POINT('',(-22.8355263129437,8.83486539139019,25.4565947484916));
#617=CARTESIAN_POINT('',(-22.8488682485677,8.99596743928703,25.2611962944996));
#618=CARTESIAN_POINT('',(-22.85629533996,9.31594223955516,24.8682503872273));
#619=CARTESIAN_POINT('',(-22.8503795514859,9.47481488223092,24.6707028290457));
#620=CARTESIAN_POINT('',(-22.812155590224,9.87212049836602,24.168845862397));
#621=CARTESIAN_POINT('',(-22.7675173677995,10.1080762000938,23.8634633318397));
#622=CARTESIAN_POINT('',(-22.6380192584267,10.5660041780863,23.2513044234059));
#623=CARTESIAN_POINT('',(-22.5532115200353,10.787994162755,22.9445303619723));
#624=CARTESIAN_POINT('',(-22.4480354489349,11.0038860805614,22.633262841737));
#625=CARTESIAN_POINT('',(-22.4464357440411,11.0071583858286,22.6285417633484));
#626=CARTESIAN_POINT('',(-22.4448315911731,11.0104284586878,22.6238207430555));
#627=B_SPLINE_CURVE_WITH_KNOTS('',3,(#611,#612,#613,#614,#615,#616,#617,#618,#619,#620,#621,
#622,#623,#624,#625,#626),.UNSPECIFIED.,.F.,.F.,(4,2,2,2,2,2,2,4),(0.,0.762310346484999,
1.52407463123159,2.28408764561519,3.04413792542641,4.20715956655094,5.36867547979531,
5.38656402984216),.UNSPECIFIED.);
#628=CARTESIAN_POINT('',(-22.5447154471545,7.70729992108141,26.796236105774));
#629=VERTEX_POINT('',#628);
#630=EDGE_CURVE('E35',#629,#180,#627,.T.);
#631=ORIENTED_EDGE('',*,*,#630,.F.);
#632=CARTESIAN_POINT('',(-22.5447989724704,7.70749992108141,26.796000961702));
#633=CARTESIAN_POINT('',(-22.4875916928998,7.57058155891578,26.9571049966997));
#634=CARTESIAN_POINT('',(-22.428846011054,7.42557716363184,27.1106361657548));
#635=CARTESIAN_POINT('',(-22.3101157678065,7.12141673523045,27.4019771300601));
#636=CARTESIAN_POINT('',(-22.2501330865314,6.9622811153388,27.5398089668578));
#637=CARTESIAN_POINT('',(-22.1312651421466,6.6333359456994,27.7981773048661));
#638=CARTESIAN_POINT('',(-22.0723751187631,6.46366628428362,27.9188906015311));
#639=CARTESIAN_POINT('',(-21.9564904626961,6.11381164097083,28.1450978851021));
#640=CARTESIAN_POINT('',(-21.899496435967,5.93362334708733,28.2505870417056));
#641=CARTESIAN_POINT('',(-21.7890087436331,5.56547946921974,28.4463413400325));
#642=CARTESIAN_POINT('',(-21.7354981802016,5.37756993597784,28.5366839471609));
#643=CARTESIAN_POINT('',(-21.6326973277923,4.99468544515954,28.7036368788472));
#644=CARTESIAN_POINT('',(-21.5834066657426,4.79971111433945,28.780248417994));
#645=CARTESIAN_POINT('',(-21.4897215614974,4.4034760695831,28.9209429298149));
#646=CARTESIAN_POINT('',(-21.4453423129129,4.20219819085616,28.9849874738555));
#647=CARTESIAN_POINT('',(-21.3622712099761,3.79510399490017,29.1013160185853));
#648=CARTESIAN_POINT('',(-21.3235807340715,3.58928659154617,29.1535971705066));
#649=CARTESIAN_POINT('',(-21.2310677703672,3.04999002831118,29.2754878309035));
#650=CARTESIAN_POINT('',(-21.1820343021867,2.71377823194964,29.3367607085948));
#651=CARTESIAN_POINT('',(-21.1009493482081,2.0358125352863,29.4355331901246));
#652=CARTESIAN_POINT('',(-21.0689064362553,1.69405592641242,29.4730207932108));
#653=CARTESIAN_POINT('',(-21.0223803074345,1.006797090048,29.5268121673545));
#654=CARTESIAN_POINT('',(-21.0079439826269,0.661287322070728,29.5430593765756));
#655=CARTESIAN_POINT('',(-20.9970330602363,-0.0303050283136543,29.5553745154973));
#656=CARTESIAN_POINT('',(-21.0005555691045,-0.376387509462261,29.5514456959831));
#657=CARTESIAN_POINT('',(-21.0257550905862,-1.07420211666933,29.5228357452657));
#658=CARTESIAN_POINT('',(-21.0478042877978,-1.42590390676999,29.4977291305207));
#659=CARTESIAN_POINT('',(-21.1101545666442,-2.1253997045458,29.4243130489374));
#660=CARTESIAN_POINT('',(-21.1504603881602,-2.47319267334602,29.3759975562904));
#661=CARTESIAN_POINT('',(-21.2482506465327,-3.16044858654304,29.2531002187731));
#662=CARTESIAN_POINT('',(-21.3056744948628,-3.4999364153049,29.1786108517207));
#663=CARTESIAN_POINT('',(-21.4360907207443,-4.16759265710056,28.9991111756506));
#664=CARTESIAN_POINT('',(-21.5090696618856,-4.49577055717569,28.8941271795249));
#665=CARTESIAN_POINT('',(-21.6362641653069,-5.00853364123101,28.6977986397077));
#666=CARTESIAN_POINT('',(-21.6864339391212,-5.19842309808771,28.6175726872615));
#667=CARTESIAN_POINT('',(-21.790525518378,-5.57076198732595,28.4435056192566));
#668=CARTESIAN_POINT('',(-21.8444460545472,-5.75321390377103,28.3496690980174));
#669=CARTESIAN_POINT('',(-21.9548433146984,-6.10872975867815,28.1479071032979));
#670=CARTESIAN_POINT('',(-22.0113133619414,-6.28181587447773,28.0400171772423));
#671=CARTESIAN_POINT('',(-22.1256348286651,-6.61738207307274,27.8095892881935));
#672=CARTESIAN_POINT('',(-22.1834855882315,-6.77986708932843,27.6870582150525));
#673=CARTESIAN_POINT('',(-22.2926436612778,-7.07507705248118,27.4418229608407));
#674=CARTESIAN_POINT('',(-22.343957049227,-7.20909576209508,27.3206799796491));
#675=CARTESIAN_POINT('',(-22.44549369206,-7.46656518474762,27.0668837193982));
#676=CARTESIAN_POINT('',(-22.4957154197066,-7.59000172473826,26.9342154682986));
#677=CARTESIAN_POINT('',(-22.5447989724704,-7.70749992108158,26.796000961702));
#678=B_SPLINE_CURVE_WITH_KNOTS('',3,(#632,#633,#634,#635,#636,#637,#638,#639,#640,#641,#642,
#643,#644,#645,#646,#647,#648,#649,#650,#651,#652,#653,#654,#655,#656,#657,#658,#659,#660,#661,
#662,#663,#664,#665,#666,#667,#668,#669,#670,#671,#672,#673,#674,#675,#676,#677),.UNSPECIFIED.,
.F.,.F.,(4,2,2,2,2,2,2,2,2,2,2,2,2,2,2,2,2,2,2,2,2,2,4),(0.,0.656643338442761,1.31235309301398,
1.96070148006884,2.60925512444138,3.25438332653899,3.89945443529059,4.54646837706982,
5.1936388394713,6.22786074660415,7.26260405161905,8.3000972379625,9.33742326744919,
10.3961007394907,11.4550532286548,12.5103012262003,13.56464137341,14.200604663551,
14.8363537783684,15.470524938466,16.1043988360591,16.6671691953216,17.2306818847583),.UNSPECIFIED.);
#679=CARTESIAN_POINT('',(-22.5447154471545,-7.70729992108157,26.796236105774));
#680=VERTEX_POINT('',#679);
#681=EDGE_CURVE('E249',#629,#680,#678,.T.);
#682=ORIENTED_EDGE('',*,*,#681,.T.);
#683=CARTESIAN_POINT('',(-22.444831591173,-11.0104284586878,22.6238207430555));
#684=CARTESIAN_POINT('',(-22.4464357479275,-11.0071583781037,22.62854177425));
#685=CARTESIAN_POINT('',(-22.4480354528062,-11.0038860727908,22.633262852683));
#686=CARTESIAN_POINT('',(-22.5292989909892,-10.8370787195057,22.8737614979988));
#687=CARTESIAN_POINT('',(-22.5978518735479,-10.6680207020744,23.1096462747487));
#688=CARTESIAN_POINT('',(-22.7115523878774,-10.3211392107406,23.5806622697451));
#689=CARTESIAN_POINT('',(-22.75669134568,-10.1433125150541,23.8157931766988));
#690=CARTESIAN_POINT('',(-22.8223990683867,-9.78080623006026,24.284849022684));
#691=CARTESIAN_POINT('',(-22.8429294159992,-9.59611638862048,24.5187715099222));
#692=CARTESIAN_POINT('',(-22.8579355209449,-9.22263939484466,24.9839347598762));
#693=CARTESIAN_POINT('',(-22.8524280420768,-9.03385495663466,25.2151771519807));
#694=CARTESIAN_POINT('',(-22.8138212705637,-8.65409842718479,25.6747306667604));
#695=CARTESIAN_POINT('',(-22.7806472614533,-8.46312179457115,25.9030321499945));
#696=CARTESIAN_POINT('',(-22.7089141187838,-8.17797071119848,26.2414212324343));
#697=CARTESIAN_POINT('',(-22.6813764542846,-8.08322589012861,26.3534392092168));
#698=CARTESIAN_POINT('',(-22.6187377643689,-7.89448609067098,26.5760679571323));
#699=CARTESIAN_POINT('',(-22.5836333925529,-7.80049146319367,26.686678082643));
#700=CARTESIAN_POINT('',(-22.5446319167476,-7.7070999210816,26.7964712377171));
#701=B_SPLINE_CURVE_WITH_KNOTS('',3,(#683,#684,#685,#686,#687,#688,#689,#690,#691,#692,#693,
#694,#695,#696,#697,#698,#699,#700),.UNSPECIFIED.,.F.,.F.,(4,2,2,2,2,2,2,2,4),(0.,
0.0178885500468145,0.911260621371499,1.80496341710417,2.70005959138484,3.59457955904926,
4.49152312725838,4.93917199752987,5.38701924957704),.UNSPECIFIED.);
#702=EDGE_CURVE('E796',#157,#680,#701,.T.);
#703=ORIENTED_EDGE('',*,*,#702,.F.);
#704=ORIENTED_EDGE('',*,*,#158,.T.);
#705=CARTESIAN_POINT('',(-17.9468752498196,-15.6706720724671,26.7964548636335));
#706=CARTESIAN_POINT('',(-18.1177987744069,-15.648643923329,26.6095132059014));
#707=CARTESIAN_POINT('',(-18.2845665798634,-15.6160053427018,26.420207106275));
#708=CARTESIAN_POINT('',(-18.6084954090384,-15.5314831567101,26.0379257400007));
#709=CARTESIAN_POINT('',(-18.7656632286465,-15.479613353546,25.844953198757));
#710=CARTESIAN_POINT('',(-19.0689959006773,-15.3587065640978,25.4565751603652));
#711=CARTESIAN_POINT('',(-19.2151852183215,-15.2897093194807,25.2611762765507));
#712=CARTESIAN_POINT('',(-19.4960047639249,-15.1361526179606,24.8682295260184));
#713=CARTESIAN_POINT('',(-19.6306344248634,-15.0515923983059,24.6706815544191));
#714=CARTESIAN_POINT('',(-19.9555959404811,-14.8198368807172,24.1688277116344));
#715=CARTESIAN_POINT('',(-20.1376177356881,-14.6632025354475,23.8634487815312));
#716=CARTESIAN_POINT('',(-20.4694412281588,-14.3220932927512,23.2512971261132));
#717=CARTESIAN_POINT('',(-20.6192843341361,-14.1376547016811,22.9445267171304));
#718=CARTESIAN_POINT('',(-20.7536626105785,-13.9386259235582,22.6332628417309));
#719=CARTESIAN_POINT('',(-20.7556966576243,-13.9356043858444,22.6285417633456));
#720=CARTESIAN_POINT('',(-20.7577265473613,-13.9325801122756,22.6238207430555));
#721=B_SPLINE_CURVE_WITH_KNOTS('',3,(#705,#706,#707,#708,#709,#710,#711,#712,#713,#714,#715,
#716,#717,#718,#719,#720),.UNSPECIFIED.,.F.,.F.,(4,2,2,2,2,2,2,4),(0.,0.762311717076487,
1.52407738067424,2.28409173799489,3.04414335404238,4.20715114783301,5.36865325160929,
5.38654180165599),.UNSPECIFIED.);
#722=CARTESIAN_POINT('',(-17.9470752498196,-15.6706463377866,26.796236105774));
#723=VERTEX_POINT('',#722);
#724=EDGE_CURVE('E798',#723,#153,#721,.T.);
#725=ORIENTED_EDGE('',*,*,#724,.F.);
#726=CARTESIAN_POINT('',(-17.9472752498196,-15.6706205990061,26.7960173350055));
#727=CARTESIAN_POINT('',(-17.8000960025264,-15.6895370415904,26.9571211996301));
#728=CARTESIAN_POINT('',(-17.6451448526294,-15.7111642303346,27.1106521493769));
#729=CARTESIAN_POINT('',(-17.3223674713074,-15.7604215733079,27.4019925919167));
#730=CARTESIAN_POINT('',(-17.1545598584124,-15.7880431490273,27.5398241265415));
#731=CARTESIAN_POINT('',(-16.8102495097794,-15.8495736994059,27.7981917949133));
#732=CARTESIAN_POINT('',(-16.633865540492,-15.8834086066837,27.9189047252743));
#733=CARTESIAN_POINT('',(-16.2729388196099,-15.9579775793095,28.1451112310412));
#734=CARTESIAN_POINT('',(-16.0883935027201,-15.9987138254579,28.2505999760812));
#735=CARTESIAN_POINT('',(-15.7143264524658,-16.0871013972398,28.446353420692));
#736=CARTESIAN_POINT('',(-15.5248361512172,-16.1347150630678,28.5366955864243));
#737=CARTESIAN_POINT('',(-15.1418469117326,-16.2371300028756,28.7036476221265));
#738=CARTESIAN_POINT('',(-14.9483483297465,-16.291930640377,28.7802587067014));
#739=CARTESIAN_POINT('',(-14.5583551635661,-16.4089153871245,28.9209523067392));
#740=CARTESIAN_POINT('',(-14.3618533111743,-16.4711212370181,28.9849963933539));
#741=CARTESIAN_POINT('',(-13.9677629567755,-16.6027276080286,29.1013240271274));
#742=CARTESIAN_POINT('',(-13.7701742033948,-16.67212986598,29.1536047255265));
#743=CARTESIAN_POINT('',(-13.2568720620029,-16.8616609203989,29.2754942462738));
#744=CARTESIAN_POINT('',(-12.9411866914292,-16.987303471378,29.3367664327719));
#745=CARTESIAN_POINT('',(-12.3135074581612,-17.2560665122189,29.4355375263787));
#746=CARTESIAN_POINT('',(-12.0015155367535,-17.3991957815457,29.4730244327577));
#747=CARTESIAN_POINT('',(-11.3830678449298,-17.7025343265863,29.5268143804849));
#748=CARTESIAN_POINT('',(-11.0766289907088,-17.8627879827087,29.5430608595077));
#749=CARTESIAN_POINT('',(-10.4722361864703,-18.1991370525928,29.5553744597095));
#750=CARTESIAN_POINT('',(-10.1742808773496,-18.3752299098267,29.5514448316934));
#751=CARTESIAN_POINT('',(-9.58255501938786,-18.7459626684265,29.5228331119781));
#752=CARTESIAN_POINT('',(-9.28899683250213,-18.9409097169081,29.4977255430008));
#753=CARTESIAN_POINT('',(-8.71439077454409,-19.3446564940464,29.4243073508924));
#754=CARTESIAN_POINT('',(-8.43334617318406,-19.5534598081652,29.3759907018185));
#755=CARTESIAN_POINT('',(-7.88706048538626,-19.9817784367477,29.2530907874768));
#756=CARTESIAN_POINT('',(-7.62176755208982,-20.2012537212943,29.1786000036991));
#757=CARTESIAN_POINT('',(-7.10876905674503,-20.6480271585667,28.9990971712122));
#758=CARTESIAN_POINT('',(-6.86104855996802,-20.8753184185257,28.8941114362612));
#759=CARTESIAN_POINT('',(-6.48058176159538,-21.2418536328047,28.6977803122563));
#760=CARTESIAN_POINT('',(-6.34121880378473,-21.3802460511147,28.6175537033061));
#761=CARTESIAN_POINT('',(-6.07081213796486,-21.6565601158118,28.4434853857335));
#762=CARTESIAN_POINT('',(-5.93976564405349,-21.7944819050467,28.3496482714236));
#763=CARTESIAN_POINT('',(-5.68708094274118,-22.0678451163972,28.1478851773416));
#764=CARTESIAN_POINT('',(-5.56542019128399,-22.2032918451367,28.0399947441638));
#765=CARTESIAN_POINT('',(-5.33197442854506,-22.470078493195,27.8095659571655));
#766=CARTESIAN_POINT('',(-5.2201848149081,-22.6014203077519,27.6870344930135));
#767=CARTESIAN_POINT('',(-5.0191052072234,-22.8435588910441,27.4417968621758));
#768=CARTESIAN_POINT('',(-4.92869795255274,-22.9550077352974,27.3206517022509));
#769=CARTESIAN_POINT('',(-4.75649074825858,-23.1716770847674,27.0668508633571));
#770=CARTESIAN_POINT('',(-4.67470230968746,-23.2768891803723,26.9341802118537));
#771=CARTESIAN_POINT('',(-4.59748765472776,-23.3781462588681,26.7959632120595));
#772=B_SPLINE_CURVE_WITH_KNOTS('',3,(#726,#727,#728,#729,#730,#731,#732,#733,#734,#735,#736,
#737,#738,#739,#740,#741,#742,#743,#744,#745,#746,#747,#748,#749,#750,#751,#752,#753,#754,#755,
#756,#757,#758,#759,#760,#761,#762,#763,#764,#765,#766,#767,#768,#769,#770,#771),.UNSPECIFIED.,
.F.,.F.,(4,2,2,2,2,2,2,2,2,2,2,2,2,2,2,2,2,2,2,2,2,2,4),(0.,0.656644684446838,1.31235577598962,
1.96070546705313,2.60926041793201,3.25438989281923,3.89946227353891,4.54647750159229,
5.19364925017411,6.22787361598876,7.26261937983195,8.30011505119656,9.33744356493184,
10.3961231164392,11.4550776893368,12.5103276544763,13.5646697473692,14.2006301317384,
14.8363763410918,15.4705446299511,16.1044156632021,16.6671921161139,17.2307109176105),.UNSPECIFIED.);
#773=CARTESIAN_POINT('',(-4.59764019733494,-23.3779462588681,26.796236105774));
#774=VERTEX_POINT('',#773);
#775=EDGE_CURVE('E257',#723,#774,#772,.T.);
#776=ORIENTED_EDGE('',*,*,#775,.T.);
#777=CARTESIAN_POINT('',(-1.68710504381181,-24.9430085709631,22.6238207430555));
#778=CARTESIAN_POINT('',(-1.69073909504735,-24.9427627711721,22.6285417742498));
#779=CARTESIAN_POINT('',(-1.69437284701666,-24.9425120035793,22.6332628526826));
#780=CARTESIAN_POINT('',(-1.87946401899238,-24.9294846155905,22.87376149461));
#781=CARTESIAN_POINT('',(-2.06014899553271,-24.9043241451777,23.1096462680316));
#782=CARTESIAN_POINT('',(-2.41740743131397,-24.8293509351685,23.5806622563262));
#783=CARTESIAN_POINT('',(-2.59397934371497,-24.779529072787,23.8157931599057));
#784=CARTESIAN_POINT('',(-2.9407728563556,-24.655180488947,24.2848490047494));
#785=CARTESIAN_POINT('',(-3.11098412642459,-24.5806153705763,24.5187714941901));
#786=CARTESIAN_POINT('',(-3.44192774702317,-24.4068725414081,24.983934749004));
#787=CARTESIAN_POINT('',(-3.60266612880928,-24.307710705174,25.2151771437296));
#788=CARTESIAN_POINT('',(-3.91224598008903,-24.084394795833,25.6747372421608));
#789=CARTESIAN_POINT('',(-4.0610536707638,-23.9601730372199,25.9030452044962));
#790=CARTESIAN_POINT('',(-4.27214053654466,-23.7554678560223,26.2414437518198));
#791=CARTESIAN_POINT('',(-4.34042478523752,-23.684244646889,26.3534648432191));
#792=CARTESIAN_POINT('',(-4.47256192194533,-23.5356227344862,26.5760997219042));
#793=CARTESIAN_POINT('',(-4.53641283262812,-23.458221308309,26.686712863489));
#794=CARTESIAN_POINT('',(-4.59779273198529,-23.3777462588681,26.796508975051));
#795=B_SPLINE_CURVE_WITH_KNOTS('',3,(#777,#778,#779,#780,#781,#782,#783,#784,#785,#786,#787,
#788,#789,#790,#791,#792,#793,#794),.UNSPECIFIED.,.F.,.F.,(4,2,2,2,2,2,2,2,4),(0.,
0.0178885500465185,0.911260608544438,1.80496339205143,2.70005957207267,3.59457955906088,
4.49154874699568,4.93921044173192,5.38707053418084),.UNSPECIFIED.);
#796=EDGE_CURVE('E292',#130,#774,#795,.T.);
#797=ORIENTED_EDGE('',*,*,#796,.F.);
#798=ORIENTED_EDGE('',*,*,#131,.T.);
#799=CARTESIAN_POINT('',(4.59779273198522,-23.3777462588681,26.796508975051));
#800=CARTESIAN_POINT('',(4.49325605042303,-23.51475719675,26.6095689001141));
#801=CARTESIAN_POINT('',(4.38160827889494,-23.6428640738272,26.4202643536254));
#802=CARTESIAN_POINT('',(4.1464493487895,-23.8811358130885,26.0379860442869));
#803=CARTESIAN_POINT('',(4.02294674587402,-23.9913134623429,25.8450150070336));
#804=CARTESIAN_POINT('',(3.76657567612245,-24.1935565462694,25.4566398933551));
#805=CARTESIAN_POINT('',(3.63372939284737,-24.2856630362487,25.2612424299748));
#806=CARTESIAN_POINT('',(3.36033897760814,-24.4520846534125,24.8682984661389));
#807=CARTESIAN_POINT('',(3.21979446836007,-24.5263989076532,24.6707518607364));
#808=CARTESIAN_POINT('',(2.85660155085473,-24.691955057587,24.1688876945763));
#809=CARTESIAN_POINT('',(2.62993299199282,-24.7712789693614,23.8634968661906));
#810=CARTESIAN_POINT('',(2.16859445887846,-24.8880997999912,23.2513212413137));
#811=CARTESIAN_POINT('',(1.9339352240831,-24.9256507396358,22.9445387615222));
#812=CARTESIAN_POINT('',(1.69437283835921,-24.9425120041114,22.6332628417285));
#813=CARTESIAN_POINT('',(1.69073908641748,-24.9427627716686,22.6285417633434));
#814=CARTESIAN_POINT('',(1.68710504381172,-24.9430085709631,22.6238207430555));
#815=B_SPLINE_CURVE_WITH_KNOTS('',3,(#799,#800,#801,#802,#803,#804,#805,#806,#807,#808,#809,
#810,#811,#812,#813,#814),.UNSPECIFIED.,.F.,.F.,(4,2,2,2,2,2,2,4),(0.,0.762307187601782,
1.52406829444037,2.2840782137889,3.04412541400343,4.20717896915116,5.3687267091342,
5.38661525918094),.UNSPECIFIED.);
#816=CARTESIAN_POINT('',(4.59764019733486,-23.3779462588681,26.796236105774));
#817=VERTEX_POINT('',#816);
#818=EDGE_CURVE('E304',#817,#126,#815,.T.);
#819=ORIENTED_EDGE('',*,*,#818,.F.);
#820=CARTESIAN_POINT('',(4.59748765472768,-23.3781462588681,26.7959632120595));
#821=CARTESIAN_POINT('',(4.68745740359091,-23.2601455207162,26.9570676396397));
#822=CARTESIAN_POINT('',(4.78366062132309,-23.1367694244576,27.1105993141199));
#823=CARTESIAN_POINT('',(4.98770324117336,-22.8818683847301,27.4019414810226));
#824=CARTESIAN_POINT('',(5.09552590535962,-22.7503552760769,27.5397740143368));
#825=CARTESIAN_POINT('',(5.32096382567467,-22.4829423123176,27.7981438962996));
#826=CARTESIAN_POINT('',(5.43845555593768,-22.3471082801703,27.9188580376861));
#827=CARTESIAN_POINT('',(5.68349322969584,-22.0718238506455,28.1450671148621));
#828=CARTESIAN_POINT('',(5.81104234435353,-21.9323723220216,28.2505572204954));
#829=CARTESIAN_POINT('',(6.07461744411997,-21.652616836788,28.4463134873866));
#830=CARTESIAN_POINT('',(6.21059510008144,-21.51232127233,28.5366571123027));
#831=CARTESIAN_POINT('',(6.49077939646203,-21.2318521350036,28.7036121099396));
#832=CARTESIAN_POINT('',(6.63498530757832,-21.0916785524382,28.7802246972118));
#833=CARTESIAN_POINT('',(6.93128941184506,-20.8124283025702,28.9209213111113));
#834=CARTESIAN_POINT('',(7.08341006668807,-20.6733562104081,28.9849669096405));
#835=CARTESIAN_POINT('',(7.39442549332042,-20.397868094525,29.1012975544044));
#836=CARTESIAN_POINT('',(7.55332189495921,-20.2614527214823,29.153579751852));
#837=CARTESIAN_POINT('',(7.97410593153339,-19.9116865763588,29.2754730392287));
#838=CARTESIAN_POINT('',(8.24075460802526,-19.7011167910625,29.3367475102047));
#839=CARTESIAN_POINT('',(8.78734257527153,-19.291912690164,29.4355231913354));
#840=CARTESIAN_POINT('',(9.06728849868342,-19.0932844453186,29.4730124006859));
#841=CARTESIAN_POINT('',(9.6392040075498,-18.7093620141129,29.5268070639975));
#842=CARTESIAN_POINT('',(9.93120356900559,-18.5241046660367,29.5430559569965));
#843=CARTESIAN_POINT('',(10.5246796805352,-18.168858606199,29.5553746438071));
#844=CARTESIAN_POINT('',(10.8261546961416,-17.9988674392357,29.551447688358));
#845=CARTESIAN_POINT('',(11.4430750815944,-17.6717820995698,29.522841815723));
#846=CARTESIAN_POINT('',(11.7586802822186,-17.515025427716,29.497737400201));
#847=CARTESIAN_POINT('',(12.3956325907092,-17.2192723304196,29.4243261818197));
#848=CARTESIAN_POINT('',(12.7169811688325,-17.0802805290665,29.3760133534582));
#849=CARTESIAN_POINT('',(13.3610540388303,-16.8213387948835,29.2531219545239));
#850=CARTESIAN_POINT('',(13.6837695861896,-16.7013239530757,29.1786358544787));
#851=CARTESIAN_POINT('',(14.3271826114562,-16.4804364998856,28.9991434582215));
#852=CARTESIAN_POINT('',(14.6478815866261,-16.3795475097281,28.8941634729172));
#853=CARTESIAN_POINT('',(15.1555460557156,-16.2333162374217,28.697841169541));
#854=CARTESIAN_POINT('',(15.3450819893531,-16.1818181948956,28.6176170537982));
#855=CARTESIAN_POINT('',(15.7195868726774,-16.0857915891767,28.4435536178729));
#856=CARTESIAN_POINT('',(15.9045573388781,-16.0412606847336,28.3497188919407));
#857=CARTESIAN_POINT('',(16.2676463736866,-15.9591067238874,28.1479603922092));
#858=CARTESIAN_POINT('',(16.4457808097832,-15.9214667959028,28.040072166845));
#859=CARTESIAN_POINT('',(16.7935555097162,-15.852686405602,27.8096475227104));
#860=CARTESIAN_POINT('',(16.9631997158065,-15.8215429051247,27.6871179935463));
#861=CARTESIAN_POINT('',(17.2734523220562,-15.7684678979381,27.4418783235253));
#862=CARTESIAN_POINT('',(17.4151836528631,-15.7458950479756,27.3207286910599));
#863=CARTESIAN_POINT('',(17.6889479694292,-15.7050898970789,27.0669174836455));
#864=CARTESIAN_POINT('',(17.8209679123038,-15.6868633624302,26.9342409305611));
#865=CARTESIAN_POINT('',(17.9472752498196,-15.6706205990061,26.796017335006));
#866=B_SPLINE_CURVE_WITH_KNOTS('',3,(#820,#821,#822,#823,#824,#825,#826,#827,#828,#829,#830,
#831,#832,#833,#834,#835,#836,#837,#838,#839,#840,#841,#842,#843,#844,#845,#846,#847,#848,#849,
#850,#851,#852,#853,#854,#855,#856,#857,#858,#859,#860,#861,#862,#863,#864,#865),.UNSPECIFIED.,
.F.,.F.,(4,2,2,2,2,2,2,2,2,2,2,2,2,2,2,2,2,2,2,2,2,2,4),(0.,0.656640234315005,1.31234690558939,
1.96069228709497,2.60924292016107,3.2543681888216,3.89943636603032,4.54644734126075,
5.1936148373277,6.2278310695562,7.26256869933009,8.30005616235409,9.3373764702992,
10.3960491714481,11.4549968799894,12.510240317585,13.5645759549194,14.2005435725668,
14.8362970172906,15.4704724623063,16.1043506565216,16.6671595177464,17.230710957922),.UNSPECIFIED.);
#867=CARTESIAN_POINT('',(17.9470752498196,-15.6706463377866,26.796236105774));
#868=VERTEX_POINT('',#867);
#869=EDGE_CURVE('E271',#817,#868,#866,.T.);
#870=ORIENTED_EDGE('',*,*,#869,.T.);
#871=CARTESIAN_POINT('',(20.7577265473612,-13.9325801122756,22.6238207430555));
#872=CARTESIAN_POINT('',(20.7556966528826,-13.935604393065,22.6285417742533));
#873=CARTESIAN_POINT('',(20.7536626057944,-13.9386259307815,22.6332628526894));
#874=CARTESIAN_POINT('',(20.6498349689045,-14.0924058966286,22.8737614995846));
#875=CARTESIAN_POINT('',(20.5377028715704,-14.2363034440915,23.1096462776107));
#876=CARTESIAN_POINT('',(20.2941449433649,-14.5082117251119,23.5806622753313));
#877=CARTESIAN_POINT('',(20.1627119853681,-14.6362165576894,23.8157931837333));
#878=CARTESIAN_POINT('',(19.8816261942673,-14.8743742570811,24.2848490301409));
#879=CARTESIAN_POINT('',(19.7319452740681,-14.9844989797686,24.5187715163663));
#880=CARTESIAN_POINT('',(19.416007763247,-15.1842331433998,24.9839347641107));
#881=CARTESIAN_POINT('',(19.2497619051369,-15.2738557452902,25.2151771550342));
#882=CARTESIAN_POINT('',(18.9015818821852,-15.4302985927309,25.6747278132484));
#883=CARTESIAN_POINT('',(18.7196066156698,-15.497056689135,25.9030264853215));
#884=CARTESIAN_POINT('',(18.4367957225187,-15.5775089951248,26.2414114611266));
#885=CARTESIAN_POINT('',(18.340976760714,-15.6010330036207,26.3534280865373));
#886=CARTESIAN_POINT('',(18.1462066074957,-15.6411562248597,26.57605417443));
#887=CARTESIAN_POINT('',(18.04725404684,-15.657752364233,26.6866629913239));
#888=CARTESIAN_POINT('',(17.9468752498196,-15.6706720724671,26.7964548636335));
#889=B_SPLINE_CURVE_WITH_KNOTS('',3,(#871,#872,#873,#874,#875,#876,#877,#878,#879,#880,#881,
#882,#883,#884,#885,#886,#887,#888),.UNSPECIFIED.,.F.,.F.,(4,2,2,2,2,2,2,2,4),(0.,
0.0178885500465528,0.911260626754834,1.80496342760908,2.70005959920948,3.59457955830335,
4.49151201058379,4.93915531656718,5.38699699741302),.UNSPECIFIED.);
#890=EDGE_CURVE('E313',#103,#868,#889,.T.);
#891=ORIENTED_EDGE('',*,*,#890,.F.);
#892=ORIENTED_EDGE('',*,*,#104,.T.);
#893=CARTESIAN_POINT('',(22.5446319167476,-7.7070999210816,26.7964712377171));
#894=CARTESIAN_POINT('',(22.6110172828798,-7.86613771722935,26.6095300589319));
#895=CARTESIAN_POINT('',(22.6661359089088,-8.02688180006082,26.4202244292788));
#896=CARTESIAN_POINT('',(22.7549031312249,-8.34967281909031,26.0379439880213));
#897=CARTESIAN_POINT('',(22.7885670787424,-8.51171873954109,25.8449719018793));
#898=CARTESIAN_POINT('',(22.835526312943,-8.83486539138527,25.4565947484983));
#899=CARTESIAN_POINT('',(22.848868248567,-8.99596743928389,25.2611962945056));
#900=CARTESIAN_POINT('',(22.8562953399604,-9.31594223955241,24.8682503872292));
#901=CARTESIAN_POINT('',(22.8503795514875,-9.4748148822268,24.6707028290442));
#902=CARTESIAN_POINT('',(22.8121555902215,-9.87212049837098,24.1688458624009));
#903=CARTESIAN_POINT('',(22.7675173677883,-10.1080762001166,23.8634633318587));
#904=CARTESIAN_POINT('',(22.6380192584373,-10.5660041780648,23.2513044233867));
#905=CARTESIAN_POINT('',(22.5532115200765,-10.7879941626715,22.9445303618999));
#906=CARTESIAN_POINT('',(22.448035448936,-11.0038860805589,22.6332628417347));
#907=CARTESIAN_POINT('',(22.4464357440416,-11.0071583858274,22.6285417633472));
#908=CARTESIAN_POINT('',(22.444831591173,-11.0104284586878,22.6238207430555));
#909=B_SPLINE_CURVE_WITH_KNOTS('',3,(#893,#894,#895,#896,#897,#898,#899,#900,#901,#902,#903,
#904,#905,#906,#907,#908),.UNSPECIFIED.,.F.,.F.,(4,2,2,2,2,2,2,4),(0.,0.762310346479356,
1.5240746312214,2.28408764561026,3.04413792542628,4.2071595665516,5.36867547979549,
5.38656402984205),.UNSPECIFIED.);
#910=CARTESIAN_POINT('',(22.5447154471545,-7.70729992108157,26.796236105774));
#911=VERTEX_POINT('',#910);
#912=EDGE_CURVE('E337',#911,#99,#909,.T.);
#913=ORIENTED_EDGE('',*,*,#912,.F.);
#914=CARTESIAN_POINT('',(22.5447989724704,-7.70749992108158,26.796000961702));
#915=CARTESIAN_POINT('',(22.4875916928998,-7.57058155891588,26.9571049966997));
#916=CARTESIAN_POINT('',(22.428846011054,-7.4255771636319,27.1106361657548));
#917=CARTESIAN_POINT('',(22.3101157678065,-7.12141673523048,27.4019771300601));
#918=CARTESIAN_POINT('',(22.2501330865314,-6.96228111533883,27.5398089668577));
#919=CARTESIAN_POINT('',(22.1312651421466,-6.63333594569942,27.7981773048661));
#920=CARTESIAN_POINT('',(22.0723751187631,-6.46366628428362,27.9188906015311));
#921=CARTESIAN_POINT('',(21.9564904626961,-6.11381164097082,28.1450978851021));
#922=CARTESIAN_POINT('',(21.899496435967,-5.93362334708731,28.2505870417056));
#923=CARTESIAN_POINT('',(21.789008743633,-5.56547946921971,28.4463413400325));
#924=CARTESIAN_POINT('',(21.7354981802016,-5.37756993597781,28.5366839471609));
#925=CARTESIAN_POINT('',(21.6326973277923,-4.99468544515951,28.7036368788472));
#926=CARTESIAN_POINT('',(21.5834066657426,-4.79971111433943,28.7802484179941));
#927=CARTESIAN_POINT('',(21.4897215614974,-4.40347606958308,28.9209429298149));
#928=CARTESIAN_POINT('',(21.4453423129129,-4.20219819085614,28.9849874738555));
#929=CARTESIAN_POINT('',(21.3622712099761,-3.79510399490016,29.1013160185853));
#930=CARTESIAN_POINT('',(21.3235807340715,-3.58928659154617,29.1535971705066));
#931=CARTESIAN_POINT('',(21.2310677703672,-3.0499900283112,29.2754878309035));
#932=CARTESIAN_POINT('',(21.1820343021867,-2.71377823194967,29.3367607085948));
#933=CARTESIAN_POINT('',(21.1009493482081,-2.03581253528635,29.4355331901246));
#934=CARTESIAN_POINT('',(21.0689064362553,-1.69405592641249,29.4730207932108));
#935=CARTESIAN_POINT('',(21.0223803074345,-1.00679709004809,29.5268121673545));
#936=CARTESIAN_POINT('',(21.007943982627,-0.661287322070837,29.5430593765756));
#937=CARTESIAN_POINT('',(20.9970330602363,0.0303050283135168,29.5553745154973));
#938=CARTESIAN_POINT('',(21.0005555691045,0.37638750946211,29.5514456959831));
#939=CARTESIAN_POINT('',(21.0257550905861,1.07420211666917,29.5228357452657));
#940=CARTESIAN_POINT('',(21.0478042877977,1.42590390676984,29.4977291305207));
#941=CARTESIAN_POINT('',(21.1101545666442,2.12539970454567,29.4243130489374));
#942=CARTESIAN_POINT('',(21.1504603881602,2.47319267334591,29.3759975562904));
#943=CARTESIAN_POINT('',(21.2482506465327,3.16044858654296,29.2531002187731));
#944=CARTESIAN_POINT('',(21.3056744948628,3.49993641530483,29.1786108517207));
#945=CARTESIAN_POINT('',(21.4360907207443,4.16759265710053,28.9991111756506));
#946=CARTESIAN_POINT('',(21.5090696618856,4.49577055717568,28.8941271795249));
#947=CARTESIAN_POINT('',(21.6362641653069,5.00853364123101,28.6977986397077));
#948=CARTESIAN_POINT('',(21.6864339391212,5.1984230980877,28.6175726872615));
#949=CARTESIAN_POINT('',(21.790525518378,5.57076198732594,28.4435056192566));
#950=CARTESIAN_POINT('',(21.8444460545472,5.75321390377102,28.3496690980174));
#951=CARTESIAN_POINT('',(21.9548433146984,6.10872975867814,28.1479071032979));
#952=CARTESIAN_POINT('',(22.0113133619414,6.28181587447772,28.0400171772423));
#953=CARTESIAN_POINT('',(22.1256348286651,6.61738207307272,27.8095892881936));
#954=CARTESIAN_POINT('',(22.1834855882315,6.77986708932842,27.6870582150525));
#955=CARTESIAN_POINT('',(22.2926436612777,7.07507705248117,27.4418229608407));
#956=CARTESIAN_POINT('',(22.343957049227,7.20909576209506,27.3206799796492));
#957=CARTESIAN_POINT('',(22.44549369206,7.46656518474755,27.0668837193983));
#958=CARTESIAN_POINT('',(22.4957154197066,7.59000172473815,26.9342154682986));
#959=CARTESIAN_POINT('',(22.5447989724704,7.70749992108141,26.796000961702));
#960=B_SPLINE_CURVE_WITH_KNOTS('',3,(#914,#915,#916,#917,#918,#919,#920,#921,#922,#923,#924,
#925,#926,#927,#928,#929,#930,#931,#932,#933,#934,#935,#936,#937,#938,#939,#940,#941,#942,#943,
#944,#945,#946,#947,#948,#949,#950,#951,#952,#953,#954,#955,#956,#957,#958,#959),.UNSPECIFIED.,
.F.,.F.,(4,2,2,2,2,2,2,2,2,2,2,2,2,2,2,2,2,2,2,2,2,2,4),(0.,0.656643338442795,1.31235309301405,
1.96070148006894,2.60925512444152,3.25438332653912,3.89945443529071,4.54646837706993,
5.19363883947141,6.22786074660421,7.26260405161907,8.30009723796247,9.33742326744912,
10.3961007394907,11.4550532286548,12.5103012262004,13.5646413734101,14.2006046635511,
14.8363537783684,15.4705249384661,16.1043988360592,16.6671691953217,17.2306818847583),.UNSPECIFIED.);
#961=CARTESIAN_POINT('',(22.5447154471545,7.70729992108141,26.796236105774));
#962=VERTEX_POINT('',#961);
#963=EDGE_CURVE('E28',#911,#962,#960,.T.);
#964=ORIENTED_EDGE('',*,*,#963,.T.);
#965=CARTESIAN_POINT('',(22.444831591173,11.0104284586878,22.6238207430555));
#966=CARTESIAN_POINT('',(22.446435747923,11.0071583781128,22.6285417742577));
#967=CARTESIAN_POINT('',(22.4480354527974,11.0038860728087,22.6332628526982));
#968=CARTESIAN_POINT('',(22.5292989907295,10.837078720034,22.8737614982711));
#969=CARTESIAN_POINT('',(22.5978518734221,10.6680207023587,23.1096462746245));
#970=CARTESIAN_POINT('',(22.7115523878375,10.3211392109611,23.5806622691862));
#971=CARTESIAN_POINT('',(22.7566913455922,10.1433125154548,23.8157931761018));
#972=CARTESIAN_POINT('',(22.8223990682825,9.78080623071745,24.2848490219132));
#973=CARTESIAN_POINT('',(22.8429294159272,9.59611638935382,24.5187715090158));
#974=CARTESIAN_POINT('',(22.8579355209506,9.22263939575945,24.9839347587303));
#975=CARTESIAN_POINT('',(22.8524280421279,9.03385495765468,25.2151771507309));
#976=CARTESIAN_POINT('',(22.8138212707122,8.65409842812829,25.6747306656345));
#977=CARTESIAN_POINT('',(22.7806472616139,8.46312179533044,25.903032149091));
#978=CARTESIAN_POINT('',(22.7089141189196,8.1779707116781,26.2414212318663));
#979=CARTESIAN_POINT('',(22.681376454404,8.08322589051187,26.353439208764));
#980=CARTESIAN_POINT('',(22.6187377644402,7.8944860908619,26.5760679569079));
#981=CARTESIAN_POINT('',(22.5836333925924,7.80049146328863,26.6866780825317));
#982=CARTESIAN_POINT('',(22.5446319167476,7.7070999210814,26.7964712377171));
#983=B_SPLINE_CURVE_WITH_KNOTS('',3,(#965,#966,#967,#968,#969,#970,#971,#972,#973,#974,#975,
#976,#977,#978,#979,#980,#981,#982),.UNSPECIFIED.,.F.,.F.,(4,2,2,2,2,2,2,2,4),(0.,
0.0178885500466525,0.911260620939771,1.80496341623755,2.70005959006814,3.59457955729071,
4.49152312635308,4.93917199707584,5.38701924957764),.UNSPECIFIED.);
#984=EDGE_CURVE('E346',#76,#962,#983,.T.);
#985=ORIENTED_EDGE('',*,*,#984,.F.);
#986=ORIENTED_EDGE('',*,*,#77,.T.);
#987=CARTESIAN_POINT('',(17.9468752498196,15.670672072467,26.7964548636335));
#988=CARTESIAN_POINT('',(18.1177987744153,15.6486439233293,26.6095132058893));
#989=CARTESIAN_POINT('',(18.2845665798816,15.6160053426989,26.4202071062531));
#990=CARTESIAN_POINT('',(18.6084954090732,15.5314831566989,26.0379257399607));
#991=CARTESIAN_POINT('',(18.7656632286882,15.4796133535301,25.8449531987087));
#992=CARTESIAN_POINT('',(19.0689959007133,15.3587065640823,25.4565751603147));
#993=CARTESIAN_POINT('',(19.2151852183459,15.2897093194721,25.2611762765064));
#994=CARTESIAN_POINT('',(19.4960047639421,15.1361526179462,24.8682295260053));
#995=CARTESIAN_POINT('',(19.6306344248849,15.0515923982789,24.670681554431));
#996=CARTESIAN_POINT('',(19.9555959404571,14.8198368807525,24.1688277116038));
#997=CARTESIAN_POINT('',(20.1376177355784,14.6632025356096,23.8634487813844));
#998=CARTESIAN_POINT('',(20.4694412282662,14.3220932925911,23.2512971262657));
#999=CARTESIAN_POINT('',(20.6192843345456,14.1376547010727,22.9445267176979));
#1000=CARTESIAN_POINT('',(20.7536626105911,13.9386259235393,22.6332628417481));
#1001=CARTESIAN_POINT('',(20.7556966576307,13.9356043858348,22.6285417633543));
#1002=CARTESIAN_POINT('',(20.7577265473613,13.9325801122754,22.6238207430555));
#1003=B_SPLINE_CURVE_WITH_KNOTS('',3,(#987,#988,#989,#990,#991,#992,#993,#994,#995,#996,#997,
#998,#999,#1000,#1001,#1002),.UNSPECIFIED.,.F.,.F.,(4,2,2,2,2,2,2,4),(0.,0.762311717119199,
1.52407738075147,2.28409173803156,3.04414335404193,4.20715114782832,5.36865325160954,
5.38654180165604),.UNSPECIFIED.);
#1004=CARTESIAN_POINT('',(17.9470752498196,15.6706463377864,26.796236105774));
#1005=VERTEX_POINT('',#1004);
#1006=EDGE_CURVE('E43',#1005,#72,#1003,.T.);
#1007=ORIENTED_EDGE('',*,*,#1006,.F.);
#1008=CARTESIAN_POINT('',(17.9472752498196,15.6706205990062,26.796017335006));
#1009=CARTESIAN_POINT('',(17.8000960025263,15.6895370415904,26.9571211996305));
#1010=CARTESIAN_POINT('',(17.6451448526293,15.7111642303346,27.1106521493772));
#1011=CARTESIAN_POINT('',(17.3223674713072,15.7604215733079,27.4019925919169));
#1012=CARTESIAN_POINT('',(17.1545598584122,15.7880431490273,27.5398241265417));
#1013=CARTESIAN_POINT('',(16.8102495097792,15.8495736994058,27.7981917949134));
#1014=CARTESIAN_POINT('',(16.6338655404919,15.8834086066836,27.9189047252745));
#1015=CARTESIAN_POINT('',(16.2729388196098,15.9579775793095,28.1451112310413));
#1016=CARTESIAN_POINT('',(16.0883935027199,15.9987138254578,28.2505999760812));
#1017=CARTESIAN_POINT('',(15.7143264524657,16.0871013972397,28.4463534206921));
#1018=CARTESIAN_POINT('',(15.5248361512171,16.1347150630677,28.5366955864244));
#1019=CARTESIAN_POINT('',(15.1418469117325,16.2371300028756,28.7036476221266));
#1020=CARTESIAN_POINT('',(14.9483483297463,16.2919306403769,28.7802587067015));
#1021=CARTESIAN_POINT('',(14.5583551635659,16.4089153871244,28.9209523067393));
#1022=CARTESIAN_POINT('',(14.3618533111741,16.4711212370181,28.984996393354));
#1023=CARTESIAN_POINT('',(13.9677629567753,16.6027276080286,29.1013240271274));
#1024=CARTESIAN_POINT('',(13.7701742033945,16.6721298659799,29.1536047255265));
#1025=CARTESIAN_POINT('',(13.2568720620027,16.8616609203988,29.2754942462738));
#1026=CARTESIAN_POINT('',(12.941186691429,16.987303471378,29.336766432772));
#1027=CARTESIAN_POINT('',(12.3135074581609,17.256066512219,29.4355375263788));
#1028=CARTESIAN_POINT('',(12.0015155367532,17.3991957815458,29.4730244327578));
#1029=CARTESIAN_POINT('',(11.3830678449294,17.7025343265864,29.526814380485));
#1030=CARTESIAN_POINT('',(11.0766289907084,17.8627879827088,29.5430608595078));
#1031=CARTESIAN_POINT('',(10.4722361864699,18.199137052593,29.5553744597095));
#1032=CARTESIAN_POINT('',(10.1742808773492,18.375229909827,29.5514448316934));
#1033=CARTESIAN_POINT('',(9.58255501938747,18.7459626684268,29.5228331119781));
#1034=CARTESIAN_POINT('',(9.28899683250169,18.9409097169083,29.4977255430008));
#1035=CARTESIAN_POINT('',(8.71439077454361,19.3446564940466,29.4243073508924));
#1036=CARTESIAN_POINT('',(8.4333461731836,19.5534598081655,29.3759907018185));
#1037=CARTESIAN_POINT('',(7.88706048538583,19.981778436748,29.2530907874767));
#1038=CARTESIAN_POINT('',(7.6217675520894,20.2012537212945,29.178600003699));
#1039=CARTESIAN_POINT('',(7.10876905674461,20.648027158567,28.9990971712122));
#1040=CARTESIAN_POINT('',(6.86104855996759,20.875318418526,28.8941114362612));
#1041=CARTESIAN_POINT('',(6.480581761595,21.241853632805,28.6977803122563));
#1042=CARTESIAN_POINT('',(6.34121880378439,21.380246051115,28.617553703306));
#1043=CARTESIAN_POINT('',(6.07081213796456,21.656560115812,28.4434853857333));
#1044=CARTESIAN_POINT('',(5.93976564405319,21.7944819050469,28.3496482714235));
#1045=CARTESIAN_POINT('',(5.68708094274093,22.0678451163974,28.1478851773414));
#1046=CARTESIAN_POINT('',(5.56542019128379,22.2032918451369,28.0399947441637));
#1047=CARTESIAN_POINT('',(5.33197442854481,22.4700784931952,27.8095659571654));
#1048=CARTESIAN_POINT('',(5.22018481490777,22.601420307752,27.6870344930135));
#1049=CARTESIAN_POINT('',(5.01910520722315,22.8435588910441,27.4417968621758));
#1050=CARTESIAN_POINT('',(4.92869795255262,22.9550077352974,27.320651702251));
#1051=CARTESIAN_POINT('',(4.75649074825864,23.1716770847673,27.0668508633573));
#1052=CARTESIAN_POINT('',(4.67470230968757,23.2768891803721,26.9341802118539));
#1053=CARTESIAN_POINT('',(4.59748765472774,23.378146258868,26.79596321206));
#1054=B_SPLINE_CURVE_WITH_KNOTS('',3,(#1008,#1009,#1010,#1011,#1012,#1013,#1014,#1015,#1016,
#1017,#1018,#1019,#1020,#1021,#1022,#1023,#1024,#1025,#1026,#1027,#1028,#1029,#1030,#1031,#1032,
#1033,#1034,#1035,#1036,#1037,#1038,#1039,#1040,#1041,#1042,#1043,#1044,#1045,#1046,#1047,#1048,
#1049,#1050,#1051,#1052,#1053),.UNSPECIFIED.,.F.,.F.,(4,2,2,2,2,2,2,2,2,2,2,2,2,2,2,2,2,2,2,2,2,
2,4),(0.,0.656644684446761,1.31235577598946,1.96070546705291,2.60926041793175,3.254389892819,
3.89946227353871,4.54647750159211,5.19364925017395,6.22787361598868,7.26261937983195,
8.30011505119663,9.33744356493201,10.3961231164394,11.455077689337,12.5103276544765,
13.5646697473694,14.2006301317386,14.8363763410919,15.4705446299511,16.1044156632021,
16.6671921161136,17.2307109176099),.UNSPECIFIED.);
#1055=EDGE_CURVE('E9',#1005,#513,#1054,.T.);
#1056=ORIENTED_EDGE('',*,*,#1055,.T.);
#1057=EDGE_LOOP('',(#515,#516,#537,#588,#609,#610,#631,#682,#703,#704,#725,#776,#797,#798,#819,
#870,#891,#892,#913,#964,#985,#986,#1007,#1056));
#1058=FACE_BOUND('',#1057,.T.);
#1059=ORIENTED_EDGE('',*,*,#472,.F.);
#1060=EDGE_LOOP('',(#1059));
#1061=FACE_BOUND('',#1060,.T.);
#1062=ADVANCED_FACE('F229',(#1058,#1061),#492,.T.);
#1063=CARTESIAN_POINT('',(0.,0.,31.));
#1064=DIRECTION('',(0.,0.,1.));
#1065=DIRECTION('',(-1.,0.,0.));
#1066=AXIS2_PLACEMENT_3D('',#1063,#1064,#1065);
#1067=CYLINDRICAL_SURFACE('',#1066,12.5);
#1068=CARTESIAN_POINT('',(0.,0.,31.));
#1069=DIRECTION('',(0.,0.,1.));
#1070=DIRECTION('',(-1.,0.,0.));
#1071=AXIS2_PLACEMENT_3D('',#1068,#1069,#1070);
#1072=CIRCLE('',#1071,12.5);
#1073=CARTESIAN_POINT('',(-12.5,0.,31.));
#1074=VERTEX_POINT('',#1073);
#1075=EDGE_CURVE('E419',#1074,#1074,#1072,.T.);
#1076=ORIENTED_EDGE('',*,*,#1075,.F.);
#1077=EDGE_LOOP('',(#1076));
#1078=FACE_BOUND('',#1077,.T.);
#1079=ORIENTED_EDGE('',*,*,#483,.T.);
#1080=EDGE_LOOP('',(#1079));
#1081=FACE_BOUND('',#1080,.T.);
#1082=ADVANCED_FACE('F388',(#1078,#1081),#1067,.F.);
#1083=CARTESIAN_POINT('',(0.,0.,31.));
#1084=DIRECTION('',(0.,0.,1.));
#1085=DIRECTION('',(-1.,0.,0.));
#1086=AXIS2_PLACEMENT_3D('',#1083,#1084,#1085);
#1087=PLANE('',#1086);
#1088=ORIENTED_EDGE('',*,*,#1075,.T.);
#1089=EDGE_LOOP('',(#1088));
#1090=FACE_BOUND('',#1089,.T.);
#1091=ADVANCED_FACE('F385',(#1090),#1087,.T.);
#1092=CARTESIAN_POINT('',(-17.4364902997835,11.7033672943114,0.));
#1093=DIRECTION('',(0.,0.,1.));
#1094=DIRECTION('',(-1.,0.,0.));
#1095=AXIS2_PLACEMENT_3D('',#1092,#1093,#1094);
#1096=CYLINDRICAL_SURFACE('',#1095,4.);
#1097=ORIENTED_EDGE('',*,*,#191,.T.);
#1098=ORIENTED_EDGE('',*,*,#608,.T.);
#1099=DIRECTION('',(0.,0.,1.));
#1100=VECTOR('',#1099,1.);
#1101=CARTESIAN_POINT('',(-17.9470752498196,15.6706463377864,0.));
#1102=LINE('',#1101,#1100);
#1103=EDGE_CURVE('E187',#338,#586,#1102,.T.);
#1104=ORIENTED_EDGE('',*,*,#1103,.F.);
#1105=ORIENTED_EDGE('',*,*,#339,.F.);
#1106=EDGE_LOOP('',(#1097,#1098,#1104,#1105));
#1107=FACE_BOUND('',#1106,.T.);
#1108=ADVANCED_FACE('F198',(#1107),#1096,.T.);
#1109=CARTESIAN_POINT('',(-1.41716823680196,20.9521271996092,0.));
#1110=DIRECTION('',(0.,0.,1.));
#1111=DIRECTION('',(-1.,0.,0.));
#1112=AXIS2_PLACEMENT_3D('',#1109,#1110,#1111);
#1113=CYLINDRICAL_SURFACE('',#1112,4.);
#1114=DIRECTION('',(0.,0.,1.));
#1115=VECTOR('',#1114,1.);
#1116=CARTESIAN_POINT('',(-4.59764019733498,23.377946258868,0.));
#1117=LINE('',#1116,#1115);
#1118=EDGE_CURVE('E190',#347,#535,#1117,.T.);
#1119=ORIENTED_EDGE('',*,*,#1118,.T.);
#1120=ORIENTED_EDGE('',*,*,#536,.T.);
#1121=ORIENTED_EDGE('',*,*,#41,.F.);
#1122=ORIENTED_EDGE('',*,*,#355,.F.);
#1123=EDGE_LOOP('',(#1119,#1120,#1121,#1122));
#1124=FACE_BOUND('',#1123,.T.);
#1125=ADVANCED_FACE('F502',(#1124),#1113,.T.);
#1126=CARTESIAN_POINT('',(-20.5,35.507041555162,0.));
#1127=DIRECTION('',(0.,0.,1.));
#1128=DIRECTION('',(-1.,0.,0.));
#1129=AXIS2_PLACEMENT_3D('',#1126,#1127,#1128);
#1130=CYLINDRICAL_SURFACE('',#1129,20.);
#1131=ORIENTED_EDGE('',*,*,#348,.T.);
#1132=ORIENTED_EDGE('',*,*,#1103,.T.);
#1133=ORIENTED_EDGE('',*,*,#587,.F.);
#1134=ORIENTED_EDGE('',*,*,#1118,.F.);
#1135=EDGE_LOOP('',(#1131,#1132,#1133,#1134));
#1136=FACE_BOUND('',#1135,.T.);
#1137=ADVANCED_FACE('F186',(#1136),#1130,.F.);
#1138=CARTESIAN_POINT('',(-18.8536585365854,-9.2487599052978,0.));
#1139=DIRECTION('',(0.,0.,1.));
#1140=DIRECTION('',(-1.,0.,0.));
#1141=AXIS2_PLACEMENT_3D('',#1138,#1139,#1140);
#1142=CYLINDRICAL_SURFACE('',#1141,4.);
#1143=ORIENTED_EDGE('',*,*,#164,.T.);
#1144=ORIENTED_EDGE('',*,*,#702,.T.);
#1145=DIRECTION('',(0.,0.,1.));
#1146=VECTOR('',#1145,1.);
#1147=CARTESIAN_POINT('',(-22.5447154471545,-7.70729992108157,0.));
#1148=LINE('',#1147,#1146);
#1149=EDGE_CURVE('E509',#312,#680,#1148,.T.);
#1150=ORIENTED_EDGE('',*,*,#1149,.F.);
#1151=ORIENTED_EDGE('',*,*,#313,.F.);
#1152=EDGE_LOOP('',(#1143,#1144,#1150,#1151));
#1153=FACE_BOUND('',#1152,.T.);
#1154=ADVANCED_FACE('F238',(#1153),#1142,.T.);
#1155=CARTESIAN_POINT('',(-18.8536585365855,9.2487599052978,0.));
#1156=DIRECTION('',(0.,0.,1.));
#1157=DIRECTION('',(-1.,0.,0.));
#1158=AXIS2_PLACEMENT_3D('',#1155,#1156,#1157);
#1159=CYLINDRICAL_SURFACE('',#1158,4.);
#1160=DIRECTION('',(0.,0.,1.));
#1161=VECTOR('',#1160,1.);
#1162=CARTESIAN_POINT('',(-22.5447154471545,7.70729992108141,0.));
#1163=LINE('',#1162,#1161);
#1164=EDGE_CURVE('E507',#321,#629,#1163,.T.);
#1165=ORIENTED_EDGE('',*,*,#1164,.T.);
#1166=ORIENTED_EDGE('',*,*,#630,.T.);
#1167=ORIENTED_EDGE('',*,*,#181,.F.);
#1168=ORIENTED_EDGE('',*,*,#329,.F.);
#1169=EDGE_LOOP('',(#1165,#1166,#1167,#1168));
#1170=FACE_BOUND('',#1169,.T.);
#1171=ADVANCED_FACE('F233',(#1170),#1159,.T.);
#1172=CARTESIAN_POINT('',(-41.,0.,0.));
#1173=DIRECTION('',(0.,0.,1.));
#1174=DIRECTION('',(-1.,0.,0.));
#1175=AXIS2_PLACEMENT_3D('',#1172,#1173,#1174);
#1176=CYLINDRICAL_SURFACE('',#1175,20.);
#1177=ORIENTED_EDGE('',*,*,#322,.T.);
#1178=ORIENTED_EDGE('',*,*,#1149,.T.);
#1179=ORIENTED_EDGE('',*,*,#681,.F.);
#1180=ORIENTED_EDGE('',*,*,#1164,.F.);
#1181=EDGE_LOOP('',(#1177,#1178,#1179,#1180));
#1182=FACE_BOUND('',#1181,.T.);
#1183=ADVANCED_FACE('F237',(#1182),#1176,.F.);
#1184=CARTESIAN_POINT('',(-1.41716823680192,-20.9521271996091,0.));
#1185=DIRECTION('',(0.,0.,1.));
#1186=DIRECTION('',(-1.,0.,0.));
#1187=AXIS2_PLACEMENT_3D('',#1184,#1185,#1186);
#1188=CYLINDRICAL_SURFACE('',#1187,4.);
#1189=ORIENTED_EDGE('',*,*,#137,.T.);
#1190=ORIENTED_EDGE('',*,*,#796,.T.);
#1191=DIRECTION('',(0.,0.,1.));
#1192=VECTOR('',#1191,1.);
#1193=CARTESIAN_POINT('',(-4.59764019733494,-23.3779462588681,0.));
#1194=LINE('',#1193,#1192);
#1195=EDGE_CURVE('E519',#286,#774,#1194,.T.);
#1196=ORIENTED_EDGE('',*,*,#1195,.F.);
#1197=ORIENTED_EDGE('',*,*,#287,.F.);
#1198=EDGE_LOOP('',(#1189,#1190,#1196,#1197));
#1199=FACE_BOUND('',#1198,.T.);
#1200=ADVANCED_FACE('F244',(#1199),#1188,.T.);
#1201=CARTESIAN_POINT('',(-17.4364902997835,-11.7033672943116,0.));
#1202=DIRECTION('',(0.,0.,1.));
#1203=DIRECTION('',(-1.,0.,0.));
#1204=AXIS2_PLACEMENT_3D('',#1201,#1202,#1203);
#1205=CYLINDRICAL_SURFACE('',#1204,4.);
#1206=DIRECTION('',(0.,0.,1.));
#1207=VECTOR('',#1206,1.);
#1208=CARTESIAN_POINT('',(-17.9470752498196,-15.6706463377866,0.));
#1209=LINE('',#1208,#1207);
#1210=EDGE_CURVE('E516',#295,#723,#1209,.T.);
#1211=ORIENTED_EDGE('',*,*,#1210,.T.);
#1212=ORIENTED_EDGE('',*,*,#724,.T.);
#1213=ORIENTED_EDGE('',*,*,#154,.F.);
#1214=ORIENTED_EDGE('',*,*,#303,.F.);
#1215=EDGE_LOOP('',(#1211,#1212,#1213,#1214));
#1216=FACE_BOUND('',#1215,.T.);
#1217=ADVANCED_FACE('F282',(#1216),#1205,.T.);
#1218=CARTESIAN_POINT('',(-20.5,-35.5070415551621,0.));
#1219=DIRECTION('',(0.,0.,1.));
#1220=DIRECTION('',(-1.,0.,0.));
#1221=AXIS2_PLACEMENT_3D('',#1218,#1219,#1220);
#1222=CYLINDRICAL_SURFACE('',#1221,20.);
#1223=ORIENTED_EDGE('',*,*,#296,.T.);
#1224=ORIENTED_EDGE('',*,*,#1195,.T.);
#1225=ORIENTED_EDGE('',*,*,#775,.F.);
#1226=ORIENTED_EDGE('',*,*,#1210,.F.);
#1227=EDGE_LOOP('',(#1223,#1224,#1225,#1226));
#1228=FACE_BOUND('',#1227,.T.);
#1229=ADVANCED_FACE('F277',(#1228),#1222,.F.);
#1230=CARTESIAN_POINT('',(17.4364902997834,-11.7033672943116,0.));
#1231=DIRECTION('',(0.,0.,1.));
#1232=DIRECTION('',(-1.,0.,0.));
#1233=AXIS2_PLACEMENT_3D('',#1230,#1231,#1232);
#1234=CYLINDRICAL_SURFACE('',#1233,4.);
#1235=ORIENTED_EDGE('',*,*,#110,.T.);
#1236=ORIENTED_EDGE('',*,*,#890,.T.);
#1237=DIRECTION('',(0.,0.,1.));
#1238=VECTOR('',#1237,1.);
#1239=CARTESIAN_POINT('',(17.9470752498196,-15.6706463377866,0.));
#1240=LINE('',#1239,#1238);
#1241=EDGE_CURVE('E529',#260,#868,#1240,.T.);
#1242=ORIENTED_EDGE('',*,*,#1241,.F.);
#1243=ORIENTED_EDGE('',*,*,#261,.F.);
#1244=EDGE_LOOP('',(#1235,#1236,#1242,#1243));
#1245=FACE_BOUND('',#1244,.T.);
#1246=ADVANCED_FACE('F281',(#1245),#1234,.T.);
#1247=CARTESIAN_POINT('',(1.41716823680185,-20.9521271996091,0.));
#1248=DIRECTION('',(0.,0.,1.));
#1249=DIRECTION('',(-1.,0.,0.));
#1250=AXIS2_PLACEMENT_3D('',#1247,#1248,#1249);
#1251=CYLINDRICAL_SURFACE('',#1250,4.);
#1252=DIRECTION('',(0.,0.,1.));
#1253=VECTOR('',#1252,1.);
#1254=CARTESIAN_POINT('',(4.59764019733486,-23.3779462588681,0.));
#1255=LINE('',#1254,#1253);
#1256=EDGE_CURVE('E526',#269,#817,#1255,.T.);
#1257=ORIENTED_EDGE('',*,*,#1256,.T.);
#1258=ORIENTED_EDGE('',*,*,#818,.T.);
#1259=ORIENTED_EDGE('',*,*,#127,.F.);
#1260=ORIENTED_EDGE('',*,*,#277,.F.);
#1261=EDGE_LOOP('',(#1257,#1258,#1259,#1260));
#1262=FACE_BOUND('',#1261,.T.);
#1263=ADVANCED_FACE('F289',(#1262),#1251,.T.);
#1264=CARTESIAN_POINT('',(20.5,-35.5070415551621,0.));
#1265=DIRECTION('',(0.,0.,1.));
#1266=DIRECTION('',(-1.,0.,0.));
#1267=AXIS2_PLACEMENT_3D('',#1264,#1265,#1266);
#1268=CYLINDRICAL_SURFACE('',#1267,20.);
#1269=ORIENTED_EDGE('',*,*,#270,.T.);
#1270=ORIENTED_EDGE('',*,*,#1241,.T.);
#1271=ORIENTED_EDGE('',*,*,#869,.F.);
#1272=ORIENTED_EDGE('',*,*,#1256,.F.);
#1273=EDGE_LOOP('',(#1269,#1270,#1271,#1272));
#1274=FACE_BOUND('',#1273,.T.);
#1275=ADVANCED_FACE('F326',(#1274),#1268,.F.);
#1276=CARTESIAN_POINT('',(18.8536585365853,9.24875990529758,0.));
#1277=DIRECTION('',(0.,0.,1.));
#1278=DIRECTION('',(-1.,0.,0.));
#1279=AXIS2_PLACEMENT_3D('',#1276,#1277,#1278);
#1280=CYLINDRICAL_SURFACE('',#1279,4.);
#1281=ORIENTED_EDGE('',*,*,#83,.T.);
#1282=ORIENTED_EDGE('',*,*,#984,.T.);
#1283=DIRECTION('',(0.,0.,1.));
#1284=VECTOR('',#1283,1.);
#1285=CARTESIAN_POINT('',(22.5447154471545,7.70729992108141,0.));
#1286=LINE('',#1285,#1284);
#1287=EDGE_CURVE('E539',#234,#962,#1286,.T.);
#1288=ORIENTED_EDGE('',*,*,#1287,.F.);
#1289=ORIENTED_EDGE('',*,*,#235,.F.);
#1290=EDGE_LOOP('',(#1281,#1282,#1288,#1289));
#1291=FACE_BOUND('',#1290,.T.);
#1292=ADVANCED_FACE('F333',(#1291),#1280,.T.);
#1293=CARTESIAN_POINT('',(18.8536585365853,-9.2487599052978,0.));
#1294=DIRECTION('',(0.,0.,1.));
#1295=DIRECTION('',(-1.,0.,0.));
#1296=AXIS2_PLACEMENT_3D('',#1293,#1294,#1295);
#1297=CYLINDRICAL_SURFACE('',#1296,4.);
#1298=DIRECTION('',(0.,0.,1.));
#1299=VECTOR('',#1298,1.);
#1300=CARTESIAN_POINT('',(22.5447154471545,-7.70729992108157,0.));
#1301=LINE('',#1300,#1299);
#1302=EDGE_CURVE('E536',#243,#911,#1301,.T.);
#1303=ORIENTED_EDGE('',*,*,#1302,.T.);
#1304=ORIENTED_EDGE('',*,*,#912,.T.);
#1305=ORIENTED_EDGE('',*,*,#100,.F.);
#1306=ORIENTED_EDGE('',*,*,#251,.F.);
#1307=EDGE_LOOP('',(#1303,#1304,#1305,#1306));
#1308=FACE_BOUND('',#1307,.T.);
#1309=ADVANCED_FACE('F328',(#1308),#1297,.T.);
#1310=CARTESIAN_POINT('',(41.,0.,0.));
#1311=DIRECTION('',(0.,0.,1.));
#1312=DIRECTION('',(-1.,0.,0.));
#1313=AXIS2_PLACEMENT_3D('',#1310,#1311,#1312);
#1314=CYLINDRICAL_SURFACE('',#1313,20.);
#1315=ORIENTED_EDGE('',*,*,#244,.T.);
#1316=ORIENTED_EDGE('',*,*,#1287,.T.);
#1317=ORIENTED_EDGE('',*,*,#963,.F.);
#1318=ORIENTED_EDGE('',*,*,#1302,.F.);
#1319=EDGE_LOOP('',(#1315,#1316,#1317,#1318));
#1320=FACE_BOUND('',#1319,.T.);
#1321=ADVANCED_FACE('F332',(#1320),#1314,.F.);
#1322=CARTESIAN_POINT('',(20.5,35.507041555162,0.));
#1323=DIRECTION('',(0.,0.,1.));
#1324=DIRECTION('',(-1.,0.,0.));
#1325=AXIS2_PLACEMENT_3D('',#1322,#1323,#1324);
#1326=CYLINDRICAL_SURFACE('',#1325,20.);
#1327=ORIENTED_EDGE('',*,*,#218,.T.);
#1328=DIRECTION('',(0.,0.,1.));
#1329=VECTOR('',#1328,1.);
#1330=CARTESIAN_POINT('',(4.59764019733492,23.377946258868,0.));
#1331=LINE('',#1330,#1329);
#1332=EDGE_CURVE('E463',#208,#513,#1331,.T.);
#1333=ORIENTED_EDGE('',*,*,#1332,.T.);
#1334=ORIENTED_EDGE('',*,*,#1055,.F.);
#1335=DIRECTION('',(0.,0.,1.));
#1336=VECTOR('',#1335,1.);
#1337=CARTESIAN_POINT('',(17.9470752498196,15.6706463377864,0.));
#1338=LINE('',#1337,#1336);
#1339=EDGE_CURVE('E459',#217,#1005,#1338,.T.);
#1340=ORIENTED_EDGE('',*,*,#1339,.F.);
#1341=EDGE_LOOP('',(#1327,#1333,#1334,#1340));
#1342=FACE_BOUND('',#1341,.T.);
#1343=ADVANCED_FACE('F362',(#1342),#1326,.F.);
#1344=CARTESIAN_POINT('',(1.41716823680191,20.9521271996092,0.));
#1345=DIRECTION('',(0.,0.,1.));
#1346=DIRECTION('',(-1.,0.,0.));
#1347=AXIS2_PLACEMENT_3D('',#1344,#1345,#1346);
#1348=CYLINDRICAL_SURFACE('',#1347,4.);
#1349=ORIENTED_EDGE('',*,*,#56,.T.);
#1350=ORIENTED_EDGE('',*,*,#514,.T.);
#1351=ORIENTED_EDGE('',*,*,#1332,.F.);
#1352=ORIENTED_EDGE('',*,*,#209,.F.);
#1353=EDGE_LOOP('',(#1349,#1350,#1351,#1352));
#1354=FACE_BOUND('',#1353,.T.);
#1355=ADVANCED_FACE('F361',(#1354),#1348,.T.);
#1356=CARTESIAN_POINT('',(17.4364902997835,11.7033672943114,0.));
#1357=DIRECTION('',(0.,0.,1.));
#1358=DIRECTION('',(-1.,0.,0.));
#1359=AXIS2_PLACEMENT_3D('',#1356,#1357,#1358);
#1360=CYLINDRICAL_SURFACE('',#1359,4.);
#1361=ORIENTED_EDGE('',*,*,#1339,.T.);
#1362=ORIENTED_EDGE('',*,*,#1006,.T.);
#1363=ORIENTED_EDGE('',*,*,#73,.F.);
#1364=ORIENTED_EDGE('',*,*,#225,.F.);
#1365=EDGE_LOOP('',(#1361,#1362,#1363,#1364));
#1366=FACE_BOUND('',#1365,.T.);
#1367=ADVANCED_FACE('F358',(#1366),#1360,.T.);
#1368=CLOSED_SHELL('',(#60,#87,#114,#141,#168,#195,#370,#390,#410,#430,#450,#459,#487,#1062,
#1082,#1091,#1108,#1125,#1137,#1154,#1171,#1183,#1200,#1217,#1229,#1246,#1263,#1275,#1292,#1309,
#1321,#1343,#1355,#1367));
#1369=MANIFOLD_SOLID_BREP('B1',#1368);
#1370=ADVANCED_BREP_SHAPE_REPRESENTATION('',(#18,#1369),#14);
#1371=SHAPE_DEFINITION_REPRESENTATION(#9,#1370);
ENDSEC;
END-ISO-10303-21;
